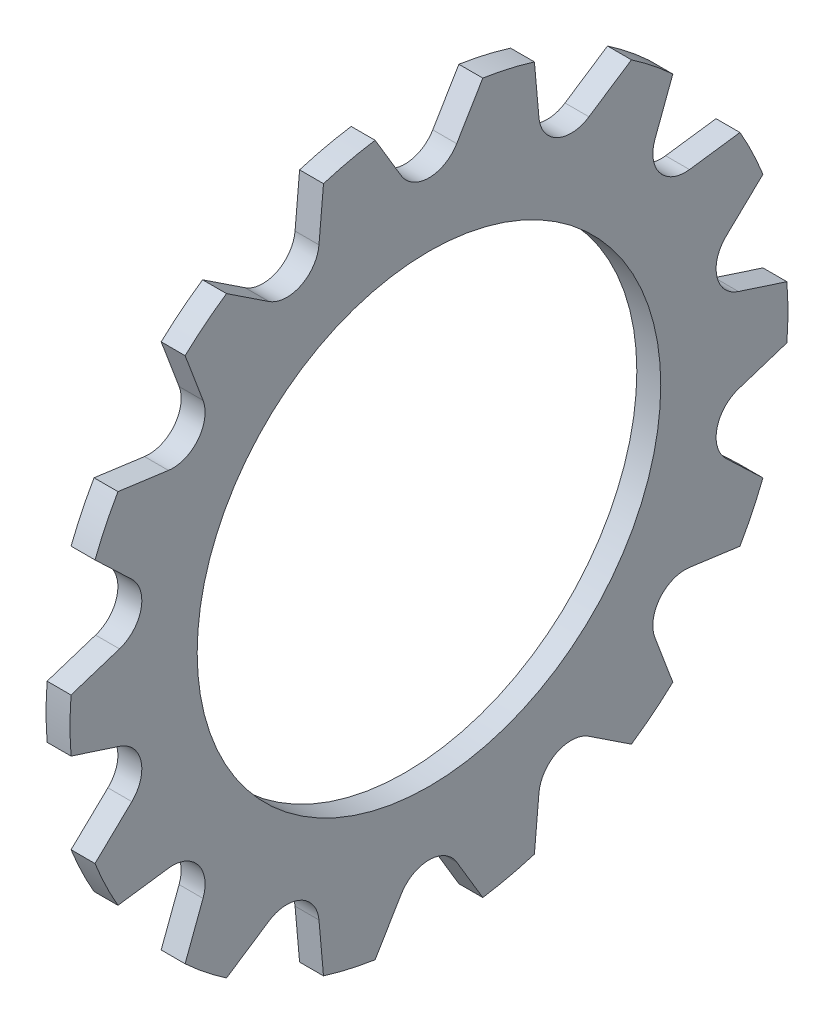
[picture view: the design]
ISO-10303-21;
HEADER;
FILE_DESCRIPTION(('STEP AP214'),'2;1');
FILE_NAME('part.step','',(''),(''),'','','');
FILE_SCHEMA(('AUTOMOTIVE_DESIGN { 1 0 10303 214 1 1 1 1 }'));
ENDSEC;
DATA;
#1=APPLICATION_CONTEXT('core data for automotive mechanical design processes');
#2=APPLICATION_PROTOCOL_DEFINITION('international standard','automotive_design',2000,#1);
#3=PRODUCT_CONTEXT('',#1,'mechanical');
#4=PRODUCT('Part','Part','',(#3));
#5=PRODUCT_RELATED_PRODUCT_CATEGORY('part','',(#4));
#6=PRODUCT_DEFINITION_FORMATION('','',#4);
#7=PRODUCT_DEFINITION_CONTEXT('part definition',#1,'design');
#8=PRODUCT_DEFINITION('design','',#6,#7);
#9=PRODUCT_DEFINITION_SHAPE('','',#8);
#10=(LENGTH_UNIT() NAMED_UNIT(*) SI_UNIT(.MILLI.,.METRE.));
#11=(NAMED_UNIT(*) PLANE_ANGLE_UNIT() SI_UNIT($,.RADIAN.));
#12=(NAMED_UNIT(*) SI_UNIT($,.STERADIAN.) SOLID_ANGLE_UNIT());
#13=UNCERTAINTY_MEASURE_WITH_UNIT(LENGTH_MEASURE(1.E-05),#10,'distance_accuracy_value','');
#14=(GEOMETRIC_REPRESENTATION_CONTEXT(3) GLOBAL_UNCERTAINTY_ASSIGNED_CONTEXT((#13)) GLOBAL_UNIT_ASSIGNED_CONTEXT((#10,
#11,#12)) REPRESENTATION_CONTEXT('',''));
#15=CARTESIAN_POINT('',(0.,0.,0.));
#16=DIRECTION('',(0.,0.,1.));
#17=DIRECTION('',(1.,0.,0.));
#18=AXIS2_PLACEMENT_3D('',#15,#16,#17);
#19=CARTESIAN_POINT('',(-1.6,0.,0.));
#20=DIRECTION('',(1.,0.,0.));
#21=DIRECTION('',(0.,0.,-1.));
#22=AXIS2_PLACEMENT_3D('',#19,#20,#21);
#23=CYLINDRICAL_SURFACE('',#22,24.);
#24=DIRECTION('',(1.,0.,0.));
#25=VECTOR('',#24,1.);
#26=CARTESIAN_POINT('',(-1.6,17.6090486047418,16.3070968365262));
#27=LINE('',#26,#25);
#28=CARTESIAN_POINT('',(-1.6,17.6090486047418,16.3070968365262));
#29=VERTEX_POINT('',#28);
#30=CARTESIAN_POINT('',(0.,17.6090486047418,16.3070968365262));
#31=VERTEX_POINT('',#30);
#32=EDGE_CURVE('E475',#29,#31,#27,.T.);
#33=ORIENTED_EDGE('',*,*,#32,.T.);
#34=CARTESIAN_POINT('',(0.,0.,0.));
#35=DIRECTION('',(1.,0.,0.));
#36=DIRECTION('',(0.,0.,-1.));
#37=AXIS2_PLACEMENT_3D('',#34,#35,#36);
#38=CIRCLE('',#37,24.);
#39=CARTESIAN_POINT('',(0.,19.8166258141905,13.5388825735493));
#40=VERTEX_POINT('',#39);
#41=EDGE_CURVE('E786',#40,#31,#38,.T.);
#42=ORIENTED_EDGE('',*,*,#41,.F.);
#43=DIRECTION('',(1.,0.,0.));
#44=VECTOR('',#43,1.);
#45=CARTESIAN_POINT('',(-1.6,19.8166258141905,13.5388825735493));
#46=LINE('',#45,#44);
#47=CARTESIAN_POINT('',(-1.6,19.8166258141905,13.5388825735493));
#48=VERTEX_POINT('',#47);
#49=EDGE_CURVE('E457',#48,#40,#46,.T.);
#50=ORIENTED_EDGE('',*,*,#49,.F.);
#51=CARTESIAN_POINT('',(-1.6,0.,0.));
#52=DIRECTION('',(1.,0.,0.));
#53=DIRECTION('',(0.,0.,-1.));
#54=AXIS2_PLACEMENT_3D('',#51,#52,#53);
#55=CIRCLE('',#54,24.);
#56=EDGE_CURVE('E41',#48,#29,#55,.T.);
#57=ORIENTED_EDGE('',*,*,#56,.T.);
#58=EDGE_LOOP('',(#33,#42,#50,#57));
#59=FACE_BOUND('',#58,.T.);
#60=ADVANCED_FACE('F32',(#59),#23,.T.);
#61=DIRECTION('',(1.,0.,0.));
#62=VECTOR('',#61,1.);
#63=CARTESIAN_POINT('',(-1.6,11.9798619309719,20.7962234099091));
#64=LINE('',#63,#62);
#65=CARTESIAN_POINT('',(-1.6,11.9798619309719,20.7962234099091));
#66=VERTEX_POINT('',#65);
#67=CARTESIAN_POINT('',(0.,11.9798619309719,20.7962234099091));
#68=VERTEX_POINT('',#67);
#69=EDGE_CURVE('E392',#66,#68,#64,.T.);
#70=ORIENTED_EDGE('',*,*,#69,.F.);
#71=CARTESIAN_POINT('',(-1.6,8.78982043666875,22.3324664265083));
#72=VERTEX_POINT('',#71);
#73=EDGE_CURVE('E407',#66,#72,#55,.T.);
#74=ORIENTED_EDGE('',*,*,#73,.T.);
#75=DIRECTION('',(1.,0.,0.));
#76=VECTOR('',#75,1.);
#77=CARTESIAN_POINT('',(-1.6,8.78982043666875,22.3324664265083));
#78=LINE('',#77,#76);
#79=CARTESIAN_POINT('',(0.,8.78982043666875,22.3324664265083));
#80=VERTEX_POINT('',#79);
#81=EDGE_CURVE('E746',#72,#80,#78,.T.);
#82=ORIENTED_EDGE('',*,*,#81,.T.);
#83=EDGE_CURVE('E409',#68,#80,#38,.T.);
#84=ORIENTED_EDGE('',*,*,#83,.F.);
#85=EDGE_LOOP('',(#70,#74,#82,#84));
#86=FACE_BOUND('',#85,.T.);
#87=ADVANCED_FACE('F405',(#86),#23,.T.);
#88=DIRECTION('',(1.,0.,0.));
#89=VECTOR('',#88,1.);
#90=CARTESIAN_POINT('',(-1.6,1.77033946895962,23.9346171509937));
#91=LINE('',#90,#89);
#92=CARTESIAN_POINT('',(-1.6,1.77033946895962,23.9346171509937));
#93=VERTEX_POINT('',#92);
#94=CARTESIAN_POINT('',(0.,1.77033946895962,23.9346171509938));
#95=VERTEX_POINT('',#94);
#96=EDGE_CURVE('E740',#93,#95,#91,.T.);
#97=ORIENTED_EDGE('',*,*,#96,.F.);
#98=CARTESIAN_POINT('',(-1.6,-1.77033946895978,23.9346171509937));
#99=VERTEX_POINT('',#98);
#100=EDGE_CURVE('E417',#93,#99,#55,.T.);
#101=ORIENTED_EDGE('',*,*,#100,.T.);
#102=DIRECTION('',(1.,0.,0.));
#103=VECTOR('',#102,1.);
#104=CARTESIAN_POINT('',(-1.6,-1.77033946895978,23.9346171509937));
#105=LINE('',#104,#103);
#106=CARTESIAN_POINT('',(0.,-1.77033946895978,23.9346171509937));
#107=VERTEX_POINT('',#106);
#108=EDGE_CURVE('E721',#99,#107,#105,.T.);
#109=ORIENTED_EDGE('',*,*,#108,.T.);
#110=EDGE_CURVE('E793',#95,#107,#38,.T.);
#111=ORIENTED_EDGE('',*,*,#110,.F.);
#112=EDGE_LOOP('',(#97,#101,#109,#111));
#113=FACE_BOUND('',#112,.T.);
#114=ADVANCED_FACE('F988',(#113),#23,.T.);
#115=DIRECTION('',(1.,0.,0.));
#116=VECTOR('',#115,1.);
#117=CARTESIAN_POINT('',(-1.6,-8.78982043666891,22.3324664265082));
#118=LINE('',#117,#116);
#119=CARTESIAN_POINT('',(-1.6,-8.78982043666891,22.3324664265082));
#120=VERTEX_POINT('',#119);
#121=CARTESIAN_POINT('',(0.,-8.78982043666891,22.3324664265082));
#122=VERTEX_POINT('',#121);
#123=EDGE_CURVE('E714',#120,#122,#118,.T.);
#124=ORIENTED_EDGE('',*,*,#123,.F.);
#125=CARTESIAN_POINT('',(-1.6,-11.9798619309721,20.796223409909));
#126=VERTEX_POINT('',#125);
#127=EDGE_CURVE('E420',#120,#126,#55,.T.);
#128=ORIENTED_EDGE('',*,*,#127,.T.);
#129=DIRECTION('',(1.,0.,0.));
#130=VECTOR('',#129,1.);
#131=CARTESIAN_POINT('',(-1.6,-11.9798619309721,20.796223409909));
#132=LINE('',#131,#130);
#133=CARTESIAN_POINT('',(0.,-11.9798619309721,20.796223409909));
#134=VERTEX_POINT('',#133);
#135=EDGE_CURVE('E695',#126,#134,#132,.T.);
#136=ORIENTED_EDGE('',*,*,#135,.T.);
#137=EDGE_CURVE('E796',#122,#134,#38,.T.);
#138=ORIENTED_EDGE('',*,*,#137,.F.);
#139=EDGE_LOOP('',(#124,#128,#136,#138));
#140=FACE_BOUND('',#139,.T.);
#141=ADVANCED_FACE('F896',(#140),#23,.T.);
#142=DIRECTION('',(1.,0.,0.));
#143=VECTOR('',#142,1.);
#144=CARTESIAN_POINT('',(-1.6,-17.6090486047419,16.3070968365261));
#145=LINE('',#144,#143);
#146=CARTESIAN_POINT('',(-1.6,-17.6090486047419,16.3070968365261));
#147=VERTEX_POINT('',#146);
#148=CARTESIAN_POINT('',(0.,-17.6090486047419,16.3070968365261));
#149=VERTEX_POINT('',#148);
#150=EDGE_CURVE('E688',#147,#149,#145,.T.);
#151=ORIENTED_EDGE('',*,*,#150,.F.);
#152=CARTESIAN_POINT('',(-1.6,-19.8166258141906,13.5388825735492));
#153=VERTEX_POINT('',#152);
#154=EDGE_CURVE('E884',#147,#153,#55,.T.);
#155=ORIENTED_EDGE('',*,*,#154,.T.);
#156=DIRECTION('',(1.,0.,0.));
#157=VECTOR('',#156,1.);
#158=CARTESIAN_POINT('',(-1.6,-19.8166258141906,13.5388825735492));
#159=LINE('',#158,#157);
#160=CARTESIAN_POINT('',(0.,-19.8166258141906,13.5388825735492));
#161=VERTEX_POINT('',#160);
#162=EDGE_CURVE('E669',#153,#161,#159,.T.);
#163=ORIENTED_EDGE('',*,*,#162,.T.);
#164=EDGE_CURVE('E801',#149,#161,#38,.T.);
#165=ORIENTED_EDGE('',*,*,#164,.F.);
#166=EDGE_LOOP('',(#151,#155,#163,#165));
#167=FACE_BOUND('',#166,.T.);
#168=ADVANCED_FACE('F906',(#167),#23,.T.);
#169=DIRECTION('',(1.,0.,0.));
#170=VECTOR('',#169,1.);
#171=CARTESIAN_POINT('',(-1.6,-22.940588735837,7.05190672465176));
#172=LINE('',#171,#170);
#173=CARTESIAN_POINT('',(-1.6,-22.940588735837,7.05190672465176));
#174=VERTEX_POINT('',#173);
#175=CARTESIAN_POINT('',(0.,-22.940588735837,7.05190672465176));
#176=VERTEX_POINT('',#175);
#177=EDGE_CURVE('E662',#174,#176,#172,.T.);
#178=ORIENTED_EDGE('',*,*,#177,.F.);
#179=CARTESIAN_POINT('',(-1.6,-23.7284639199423,3.59999999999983));
#180=VERTEX_POINT('',#179);
#181=EDGE_CURVE('E879',#174,#180,#55,.T.);
#182=ORIENTED_EDGE('',*,*,#181,.T.);
#183=DIRECTION('',(1.,0.,0.));
#184=VECTOR('',#183,1.);
#185=CARTESIAN_POINT('',(-1.6,-23.7284639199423,3.59999999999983));
#186=LINE('',#185,#184);
#187=CARTESIAN_POINT('',(0.,-23.7284639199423,3.59999999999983));
#188=VERTEX_POINT('',#187);
#189=EDGE_CURVE('E643',#180,#188,#186,.T.);
#190=ORIENTED_EDGE('',*,*,#189,.T.);
#191=EDGE_CURVE('E806',#176,#188,#38,.T.);
#192=ORIENTED_EDGE('',*,*,#191,.F.);
#193=EDGE_LOOP('',(#178,#182,#190,#192));
#194=FACE_BOUND('',#193,.T.);
#195=ADVANCED_FACE('F916',(#194),#23,.T.);
#196=DIRECTION('',(1.,0.,0.));
#197=VECTOR('',#196,1.);
#198=CARTESIAN_POINT('',(-1.6,-23.7284639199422,-3.60000000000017));
#199=LINE('',#198,#197);
#200=CARTESIAN_POINT('',(-1.6,-23.7284639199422,-3.60000000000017));
#201=VERTEX_POINT('',#200);
#202=CARTESIAN_POINT('',(0.,-23.7284639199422,-3.60000000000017));
#203=VERTEX_POINT('',#202);
#204=EDGE_CURVE('E636',#201,#203,#199,.T.);
#205=ORIENTED_EDGE('',*,*,#204,.F.);
#206=CARTESIAN_POINT('',(-1.6,-22.9405887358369,-7.05190672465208));
#207=VERTEX_POINT('',#206);
#208=EDGE_CURVE('E874',#201,#207,#55,.T.);
#209=ORIENTED_EDGE('',*,*,#208,.T.);
#210=DIRECTION('',(1.,0.,0.));
#211=VECTOR('',#210,1.);
#212=CARTESIAN_POINT('',(-1.6,-22.9405887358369,-7.05190672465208));
#213=LINE('',#212,#211);
#214=CARTESIAN_POINT('',(0.,-22.9405887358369,-7.05190672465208));
#215=VERTEX_POINT('',#214);
#216=EDGE_CURVE('E617',#207,#215,#213,.T.);
#217=ORIENTED_EDGE('',*,*,#216,.T.);
#218=EDGE_CURVE('E811',#203,#215,#38,.T.);
#219=ORIENTED_EDGE('',*,*,#218,.F.);
#220=EDGE_LOOP('',(#205,#209,#217,#219));
#221=FACE_BOUND('',#220,.T.);
#222=ADVANCED_FACE('F926',(#221),#23,.T.);
#223=DIRECTION('',(1.,0.,0.));
#224=VECTOR('',#223,1.);
#225=CARTESIAN_POINT('',(-1.6,-19.8166258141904,-13.5388825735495));
#226=LINE('',#225,#224);
#227=CARTESIAN_POINT('',(-1.6,-19.8166258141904,-13.5388825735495));
#228=VERTEX_POINT('',#227);
#229=CARTESIAN_POINT('',(0.,-19.8166258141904,-13.5388825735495));
#230=VERTEX_POINT('',#229);
#231=EDGE_CURVE('E610',#228,#230,#226,.T.);
#232=ORIENTED_EDGE('',*,*,#231,.F.);
#233=CARTESIAN_POINT('',(-1.6,-17.6090486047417,-16.3070968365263));
#234=VERTEX_POINT('',#233);
#235=EDGE_CURVE('E869',#228,#234,#55,.T.);
#236=ORIENTED_EDGE('',*,*,#235,.T.);
#237=DIRECTION('',(1.,0.,0.));
#238=VECTOR('',#237,1.);
#239=CARTESIAN_POINT('',(-1.6,-17.6090486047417,-16.3070968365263));
#240=LINE('',#239,#238);
#241=CARTESIAN_POINT('',(0.,-17.6090486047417,-16.3070968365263));
#242=VERTEX_POINT('',#241);
#243=EDGE_CURVE('E591',#234,#242,#240,.T.);
#244=ORIENTED_EDGE('',*,*,#243,.T.);
#245=EDGE_CURVE('E816',#230,#242,#38,.T.);
#246=ORIENTED_EDGE('',*,*,#245,.F.);
#247=EDGE_LOOP('',(#232,#236,#244,#246));
#248=FACE_BOUND('',#247,.T.);
#249=ADVANCED_FACE('F936',(#248),#23,.T.);
#250=DIRECTION('',(1.,0.,0.));
#251=VECTOR('',#250,1.);
#252=CARTESIAN_POINT('',(-1.6,-11.9798619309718,-20.7962234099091));
#253=LINE('',#252,#251);
#254=CARTESIAN_POINT('',(-1.6,-11.9798619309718,-20.7962234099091));
#255=VERTEX_POINT('',#254);
#256=CARTESIAN_POINT('',(0.,-11.9798619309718,-20.7962234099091));
#257=VERTEX_POINT('',#256);
#258=EDGE_CURVE('E584',#255,#257,#253,.T.);
#259=ORIENTED_EDGE('',*,*,#258,.F.);
#260=CARTESIAN_POINT('',(-1.6,-8.7898204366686,-22.3324664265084));
#261=VERTEX_POINT('',#260);
#262=EDGE_CURVE('E864',#255,#261,#55,.T.);
#263=ORIENTED_EDGE('',*,*,#262,.T.);
#264=DIRECTION('',(1.,0.,0.));
#265=VECTOR('',#264,1.);
#266=CARTESIAN_POINT('',(-1.6,-8.7898204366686,-22.3324664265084));
#267=LINE('',#266,#265);
#268=CARTESIAN_POINT('',(0.,-8.7898204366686,-22.3324664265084));
#269=VERTEX_POINT('',#268);
#270=EDGE_CURVE('E565',#261,#269,#267,.T.);
#271=ORIENTED_EDGE('',*,*,#270,.T.);
#272=EDGE_CURVE('E821',#257,#269,#38,.T.);
#273=ORIENTED_EDGE('',*,*,#272,.F.);
#274=EDGE_LOOP('',(#259,#263,#271,#273));
#275=FACE_BOUND('',#274,.T.);
#276=ADVANCED_FACE('F946',(#275),#23,.T.);
#277=DIRECTION('',(1.,0.,0.));
#278=VECTOR('',#277,1.);
#279=CARTESIAN_POINT('',(-1.6,-1.77033946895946,-23.9346171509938));
#280=LINE('',#279,#278);
#281=CARTESIAN_POINT('',(-1.6,-1.77033946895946,-23.9346171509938));
#282=VERTEX_POINT('',#281);
#283=CARTESIAN_POINT('',(0.,-1.77033946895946,-23.9346171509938));
#284=VERTEX_POINT('',#283);
#285=EDGE_CURVE('E558',#282,#284,#280,.T.);
#286=ORIENTED_EDGE('',*,*,#285,.F.);
#287=CARTESIAN_POINT('',(-1.6,1.77033946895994,-23.9346171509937));
#288=VERTEX_POINT('',#287);
#289=EDGE_CURVE('E859',#282,#288,#55,.T.);
#290=ORIENTED_EDGE('',*,*,#289,.T.);
#291=DIRECTION('',(1.,0.,0.));
#292=VECTOR('',#291,1.);
#293=CARTESIAN_POINT('',(-1.6,1.77033946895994,-23.9346171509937));
#294=LINE('',#293,#292);
#295=CARTESIAN_POINT('',(0.,1.77033946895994,-23.9346171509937));
#296=VERTEX_POINT('',#295);
#297=EDGE_CURVE('E539',#288,#296,#294,.T.);
#298=ORIENTED_EDGE('',*,*,#297,.T.);
#299=EDGE_CURVE('E826',#284,#296,#38,.T.);
#300=ORIENTED_EDGE('',*,*,#299,.F.);
#301=EDGE_LOOP('',(#286,#290,#298,#300));
#302=FACE_BOUND('',#301,.T.);
#303=ADVANCED_FACE('F956',(#302),#23,.T.);
#304=DIRECTION('',(1.,0.,0.));
#305=VECTOR('',#304,1.);
#306=CARTESIAN_POINT('',(-1.6,8.78982043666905,-22.3324664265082));
#307=LINE('',#306,#305);
#308=CARTESIAN_POINT('',(-1.6,8.78982043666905,-22.3324664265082));
#309=VERTEX_POINT('',#308);
#310=CARTESIAN_POINT('',(0.,8.78982043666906,-22.3324664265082));
#311=VERTEX_POINT('',#310);
#312=EDGE_CURVE('E532',#309,#311,#307,.T.);
#313=ORIENTED_EDGE('',*,*,#312,.F.);
#314=CARTESIAN_POINT('',(-1.6,11.9798619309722,-20.7962234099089));
#315=VERTEX_POINT('',#314);
#316=EDGE_CURVE('E855',#309,#315,#55,.T.);
#317=ORIENTED_EDGE('',*,*,#316,.T.);
#318=DIRECTION('',(1.,0.,0.));
#319=VECTOR('',#318,1.);
#320=CARTESIAN_POINT('',(-1.6,11.9798619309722,-20.7962234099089));
#321=LINE('',#320,#319);
#322=CARTESIAN_POINT('',(0.,11.9798619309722,-20.7962234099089));
#323=VERTEX_POINT('',#322);
#324=EDGE_CURVE('E514',#315,#323,#321,.T.);
#325=ORIENTED_EDGE('',*,*,#324,.T.);
#326=EDGE_CURVE('E831',#311,#323,#38,.T.);
#327=ORIENTED_EDGE('',*,*,#326,.F.);
#328=EDGE_LOOP('',(#313,#317,#325,#327));
#329=FACE_BOUND('',#328,.T.);
#330=ADVANCED_FACE('F966',(#329),#23,.T.);
#331=DIRECTION('',(1.,0.,0.));
#332=VECTOR('',#331,1.);
#333=CARTESIAN_POINT('',(-1.6,17.609048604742,-16.3070968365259));
#334=LINE('',#333,#332);
#335=CARTESIAN_POINT('',(-1.6,17.609048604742,-16.3070968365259));
#336=VERTEX_POINT('',#335);
#337=CARTESIAN_POINT('',(0.,17.609048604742,-16.3070968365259));
#338=VERTEX_POINT('',#337);
#339=EDGE_CURVE('E57',#336,#338,#334,.T.);
#340=ORIENTED_EDGE('',*,*,#339,.F.);
#341=CARTESIAN_POINT('',(-1.6,19.8166258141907,-13.5388825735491));
#342=VERTEX_POINT('',#341);
#343=EDGE_CURVE('E853',#336,#342,#55,.T.);
#344=ORIENTED_EDGE('',*,*,#343,.T.);
#345=DIRECTION('',(1.,0.,0.));
#346=VECTOR('',#345,1.);
#347=CARTESIAN_POINT('',(-1.6,19.8166258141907,-13.5388825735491));
#348=LINE('',#347,#346);
#349=CARTESIAN_POINT('',(0.,19.8166258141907,-13.5388825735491));
#350=VERTEX_POINT('',#349);
#351=EDGE_CURVE('E489',#342,#350,#348,.T.);
#352=ORIENTED_EDGE('',*,*,#351,.T.);
#353=EDGE_CURVE('E836',#338,#350,#38,.T.);
#354=ORIENTED_EDGE('',*,*,#353,.F.);
#355=EDGE_LOOP('',(#340,#344,#352,#354));
#356=FACE_BOUND('',#355,.T.);
#357=ADVANCED_FACE('F997',(#356),#23,.T.);
#358=DIRECTION('',(1.,0.,0.));
#359=VECTOR('',#358,1.);
#360=CARTESIAN_POINT('',(-1.6,22.940588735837,7.05190672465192));
#361=LINE('',#360,#359);
#362=CARTESIAN_POINT('',(-1.6,22.940588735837,7.05190672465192));
#363=VERTEX_POINT('',#362);
#364=CARTESIAN_POINT('',(0.,22.940588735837,7.05190672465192));
#365=VERTEX_POINT('',#364);
#366=EDGE_CURVE('E449',#363,#365,#361,.T.);
#367=ORIENTED_EDGE('',*,*,#366,.T.);
#368=CARTESIAN_POINT('',(0.,23.7284639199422,3.6));
#369=VERTEX_POINT('',#368);
#370=EDGE_CURVE('E36',#369,#365,#38,.T.);
#371=ORIENTED_EDGE('',*,*,#370,.F.);
#372=DIRECTION('',(1.,0.,0.));
#373=VECTOR('',#372,1.);
#374=CARTESIAN_POINT('',(-1.6,23.7284639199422,3.6));
#375=LINE('',#374,#373);
#376=CARTESIAN_POINT('',(-1.6,23.7284639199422,3.6));
#377=VERTEX_POINT('',#376);
#378=EDGE_CURVE('E430',#377,#369,#375,.T.);
#379=ORIENTED_EDGE('',*,*,#378,.F.);
#380=EDGE_CURVE('E11',#377,#363,#55,.T.);
#381=ORIENTED_EDGE('',*,*,#380,.T.);
#382=EDGE_LOOP('',(#367,#371,#379,#381));
#383=FACE_BOUND('',#382,.T.);
#384=ADVANCED_FACE('F990',(#383),#23,.T.);
#385=DIRECTION('',(1.,0.,0.));
#386=VECTOR('',#385,1.);
#387=CARTESIAN_POINT('',(-1.6,22.940588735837,-7.0519067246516));
#388=LINE('',#387,#386);
#389=CARTESIAN_POINT('',(-1.6,22.940588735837,-7.0519067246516));
#390=VERTEX_POINT('',#389);
#391=CARTESIAN_POINT('',(0.,22.9405887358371,-7.0519067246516));
#392=VERTEX_POINT('',#391);
#393=EDGE_CURVE('E49',#390,#392,#388,.T.);
#394=ORIENTED_EDGE('',*,*,#393,.F.);
#395=CARTESIAN_POINT('',(-1.6,23.7284639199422,-3.6));
#396=VERTEX_POINT('',#395);
#397=EDGE_CURVE('E42',#390,#396,#55,.T.);
#398=ORIENTED_EDGE('',*,*,#397,.T.);
#399=DIRECTION('',(1.,0.,0.));
#400=VECTOR('',#399,1.);
#401=CARTESIAN_POINT('',(-1.6,23.7284639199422,-3.6));
#402=LINE('',#401,#400);
#403=CARTESIAN_POINT('',(0.,23.7284639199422,-3.6));
#404=VERTEX_POINT('',#403);
#405=EDGE_CURVE('E426',#396,#404,#402,.T.);
#406=ORIENTED_EDGE('',*,*,#405,.T.);
#407=EDGE_CURVE('E429',#392,#404,#38,.T.);
#408=ORIENTED_EDGE('',*,*,#407,.F.);
#409=EDGE_LOOP('',(#394,#398,#406,#408));
#410=FACE_BOUND('',#409,.T.);
#411=ADVANCED_FACE('F34',(#410),#23,.T.);
#412=CARTESIAN_POINT('',(-1.6,0.,0.));
#413=DIRECTION('',(1.,0.,0.));
#414=DIRECTION('',(0.,0.,-1.));
#415=AXIS2_PLACEMENT_3D('',#412,#413,#414);
#416=PLANE('',#415);
#417=CARTESIAN_POINT('',(-1.6,0.,0.));
#418=DIRECTION('',(1.,0.,0.));
#419=DIRECTION('',(0.,0.,-1.));
#420=AXIS2_PLACEMENT_3D('',#417,#418,#419);
#421=CIRCLE('',#420,15.5);
#422=CARTESIAN_POINT('',(-1.6,0.,-15.5));
#423=VERTEX_POINT('',#422);
#424=EDGE_CURVE('E425',#423,#423,#421,.T.);
#425=ORIENTED_EDGE('',*,*,#424,.T.);
#426=EDGE_LOOP('',(#425));
#427=FACE_BOUND('',#426,.T.);
#428=CARTESIAN_POINT('',(-1.6,13.6606615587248,17.1299277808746));
#429=DIRECTION('',(1.,0.,0.));
#430=DIRECTION('',(0.,0.781831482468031,-0.623489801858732));
#431=AXIS2_PLACEMENT_3D('',#428,#429,#430);
#432=CIRCLE('',#431,2.16);
#433=CARTESIAN_POINT('',(-1.6,11.520404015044,17.4212997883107));
#434=VERTEX_POINT('',#433);
#435=CARTESIAN_POINT('',(-1.6,14.4209803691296,15.1081673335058));
#436=VERTEX_POINT('',#435);
#437=EDGE_CURVE('E399',#434,#436,#432,.T.);
#438=ORIENTED_EDGE('',*,*,#437,.T.);
#439=DIRECTION('',(0.,0.936000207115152,0.35199944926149));
#440=VECTOR('',#439,1.);
#441=CARTESIAN_POINT('',(-1.6,14.4209803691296,15.1081673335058));
#442=LINE('',#441,#440);
#443=EDGE_CURVE('E410',#436,#29,#442,.T.);
#444=ORIENTED_EDGE('',*,*,#443,.T.);
#445=ORIENTED_EDGE('',*,*,#56,.F.);
#446=DIRECTION('',(0.,-0.551453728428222,-0.834205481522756));
#447=VECTOR('',#446,1.);
#448=CARTESIAN_POINT('',(-1.6,17.9383440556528,10.6975327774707));
#449=LINE('',#448,#447);
#450=CARTESIAN_POINT('',(-1.6,17.9383440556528,10.6975327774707));
#451=VERTEX_POINT('',#450);
#452=EDGE_CURVE('E468',#48,#451,#449,.T.);
#453=ORIENTED_EDGE('',*,*,#452,.T.);
#454=CARTESIAN_POINT('',(-1.6,19.740227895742,9.50639272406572));
#455=DIRECTION('',(1.,0.,0.));
#456=DIRECTION('',(0.,0.433883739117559,-0.900968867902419));
#457=AXIS2_PLACEMENT_3D('',#454,#455,#456);
#458=CIRCLE('',#457,2.16);
#459=CARTESIAN_POINT('',(-1.6,19.548042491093,7.35495953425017));
#460=VERTEX_POINT('',#459);
#461=EDGE_CURVE('E478',#451,#460,#458,.T.);
#462=ORIENTED_EDGE('',*,*,#461,.T.);
#463=DIRECTION('',(0.,0.996033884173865,-0.0889747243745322));
#464=VECTOR('',#463,1.);
#465=CARTESIAN_POINT('',(-1.6,19.548042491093,7.35495953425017));
#466=LINE('',#465,#464);
#467=EDGE_CURVE('E460',#460,#363,#466,.T.);
#468=ORIENTED_EDGE('',*,*,#467,.T.);
#469=ORIENTED_EDGE('',*,*,#380,.F.);
#470=DIRECTION('',(0.,-0.858790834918,-0.512326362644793));
#471=VECTOR('',#470,1.);
#472=CARTESIAN_POINT('',(-1.6,20.8033750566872,1.85498820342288));
#473=LINE('',#472,#471);
#474=CARTESIAN_POINT('',(-1.6,20.8033750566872,1.85498820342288));
#475=VERTEX_POINT('',#474);
#476=EDGE_CURVE('E442',#377,#475,#473,.T.);
#477=ORIENTED_EDGE('',*,*,#476,.T.);
#478=CARTESIAN_POINT('',(-1.6,21.91,0.));
#479=DIRECTION('',(1.,0.,0.));
#480=DIRECTION('',(0.,0.,-1.));
#481=AXIS2_PLACEMENT_3D('',#478,#479,#480);
#482=CIRCLE('',#481,2.16);
#483=CARTESIAN_POINT('',(-1.6,20.8033750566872,-1.85498820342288));
#484=VERTEX_POINT('',#483);
#485=EDGE_CURVE('E452',#475,#484,#482,.T.);
#486=ORIENTED_EDGE('',*,*,#485,.T.);
#487=DIRECTION('',(0.,0.858790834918,-0.512326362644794));
#488=VECTOR('',#487,1.);
#489=CARTESIAN_POINT('',(-1.6,20.8033750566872,-1.85498820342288));
#490=LINE('',#489,#488);
#491=EDGE_CURVE('E433',#484,#396,#490,.T.);
#492=ORIENTED_EDGE('',*,*,#491,.T.);
#493=ORIENTED_EDGE('',*,*,#397,.F.);
#494=DIRECTION('',(0.,-0.996033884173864,-0.088974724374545));
#495=VECTOR('',#494,1.);
#496=CARTESIAN_POINT('',(-1.6,19.5480424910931,-7.35495953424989));
#497=LINE('',#496,#495);
#498=CARTESIAN_POINT('',(-1.6,19.5480424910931,-7.35495953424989));
#499=VERTEX_POINT('',#498);
#500=EDGE_CURVE('E495',#390,#499,#497,.T.);
#501=ORIENTED_EDGE('',*,*,#500,.T.);
#502=CARTESIAN_POINT('',(-1.6,19.7402278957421,-9.50639272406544));
#503=DIRECTION('',(1.,0.,0.));
#504=DIRECTION('',(0.,-0.433883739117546,-0.900968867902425));
#505=AXIS2_PLACEMENT_3D('',#502,#503,#504);
#506=CIRCLE('',#505,2.16);
#507=CARTESIAN_POINT('',(-1.6,17.938344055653,-10.6975327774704));
#508=VERTEX_POINT('',#507);
#509=EDGE_CURVE('E503',#499,#508,#506,.T.);
#510=ORIENTED_EDGE('',*,*,#509,.T.);
#511=DIRECTION('',(0.,0.551453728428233,-0.834205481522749));
#512=VECTOR('',#511,1.);
#513=CARTESIAN_POINT('',(-1.6,17.938344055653,-10.6975327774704));
#514=LINE('',#513,#512);
#515=EDGE_CURVE('E485',#508,#342,#514,.T.);
#516=ORIENTED_EDGE('',*,*,#515,.T.);
#517=ORIENTED_EDGE('',*,*,#343,.F.);
#518=DIRECTION('',(0.,-0.936000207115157,0.351999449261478));
#519=VECTOR('',#518,1.);
#520=CARTESIAN_POINT('',(-1.6,14.4209803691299,-15.1081673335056));
#521=LINE('',#520,#519);
#522=CARTESIAN_POINT('',(-1.6,14.4209803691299,-15.1081673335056));
#523=VERTEX_POINT('',#522);
#524=EDGE_CURVE('E520',#336,#523,#521,.T.);
#525=ORIENTED_EDGE('',*,*,#524,.T.);
#526=CARTESIAN_POINT('',(-1.6,13.6606615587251,-17.1299277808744));
#527=DIRECTION('',(1.,0.,0.));
#528=DIRECTION('',(0.,-0.781831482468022,-0.623489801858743));
#529=AXIS2_PLACEMENT_3D('',#526,#527,#528);
#530=CIRCLE('',#529,2.16);
#531=CARTESIAN_POINT('',(-1.6,11.5204040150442,-17.4212997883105));
#532=VERTEX_POINT('',#531);
#533=EDGE_CURVE('E527',#523,#532,#530,.T.);
#534=ORIENTED_EDGE('',*,*,#533,.T.);
#535=DIRECTION('',(0.,0.134894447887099,-0.990859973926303));
#536=VECTOR('',#535,1.);
#537=CARTESIAN_POINT('',(-1.6,11.5204040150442,-17.4212997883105));
#538=LINE('',#537,#536);
#539=EDGE_CURVE('E510',#532,#315,#538,.T.);
#540=ORIENTED_EDGE('',*,*,#539,.T.);
#541=ORIENTED_EDGE('',*,*,#316,.F.);
#542=DIRECTION('',(0.,-0.69058020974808,0.723255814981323));
#543=VECTOR('',#542,1.);
#544=CARTESIAN_POINT('',(-1.6,6.43766622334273,-19.8690173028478));
#545=LINE('',#544,#543);
#546=CARTESIAN_POINT('',(-1.6,6.43766622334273,-19.8690173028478));
#547=VERTEX_POINT('',#546);
#548=EDGE_CURVE('E545',#309,#547,#545,.T.);
#549=ORIENTED_EDGE('',*,*,#548,.T.);
#550=CARTESIAN_POINT('',(-1.6,4.87543366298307,-21.3606705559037));
#551=DIRECTION('',(1.,0.,0.));
#552=DIRECTION('',(0.,-0.974927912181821,-0.222520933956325));
#553=AXIS2_PLACEMENT_3D('',#550,#551,#552);
#554=CIRCLE('',#553,2.16);
#555=CARTESIAN_POINT('',(-1.6,2.82070667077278,-20.6945647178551));
#556=VERTEX_POINT('',#555);
#557=EDGE_CURVE('E553',#547,#556,#554,.T.);
#558=ORIENTED_EDGE('',*,*,#557,.T.);
#559=DIRECTION('',(0.,-0.308382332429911,-0.951262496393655));
#560=VECTOR('',#559,1.);
#561=CARTESIAN_POINT('',(-1.6,2.82070667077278,-20.6945647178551));
#562=LINE('',#561,#560);
#563=EDGE_CURVE('E535',#556,#288,#562,.T.);
#564=ORIENTED_EDGE('',*,*,#563,.T.);
#565=ORIENTED_EDGE('',*,*,#289,.F.);
#566=DIRECTION('',(0.,-0.308382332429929,0.951262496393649));
#567=VECTOR('',#566,1.);
#568=CARTESIAN_POINT('',(-1.6,-2.82070667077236,-20.6945647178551));
#569=LINE('',#568,#567);
#570=CARTESIAN_POINT('',(-1.6,-2.82070667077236,-20.6945647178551));
#571=VERTEX_POINT('',#570);
#572=EDGE_CURVE('E571',#282,#571,#569,.T.);
#573=ORIENTED_EDGE('',*,*,#572,.T.);
#574=CARTESIAN_POINT('',(-1.6,-4.87543366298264,-21.3606705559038));
#575=DIRECTION('',(1.,0.,0.));
#576=DIRECTION('',(0.,-0.974927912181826,0.222520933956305));
#577=AXIS2_PLACEMENT_3D('',#574,#575,#576);
#578=CIRCLE('',#577,2.16);
#579=CARTESIAN_POINT('',(-1.6,-6.43766622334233,-19.869017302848));
#580=VERTEX_POINT('',#579);
#581=EDGE_CURVE('E579',#571,#580,#578,.T.);
#582=ORIENTED_EDGE('',*,*,#581,.T.);
#583=DIRECTION('',(0.,-0.690580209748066,-0.723255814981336));
#584=VECTOR('',#583,1.);
#585=CARTESIAN_POINT('',(-1.6,-6.43766622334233,-19.869017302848));
#586=LINE('',#585,#584);
#587=EDGE_CURVE('E561',#580,#261,#586,.T.);
#588=ORIENTED_EDGE('',*,*,#587,.T.);
#589=ORIENTED_EDGE('',*,*,#262,.F.);
#590=DIRECTION('',(0.,0.13489444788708,0.990859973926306));
#591=VECTOR('',#590,1.);
#592=CARTESIAN_POINT('',(-1.6,-11.5204040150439,-17.4212997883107));
#593=LINE('',#592,#591);
#594=CARTESIAN_POINT('',(-1.6,-11.5204040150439,-17.4212997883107));
#595=VERTEX_POINT('',#594);
#596=EDGE_CURVE('E597',#255,#595,#593,.T.);
#597=ORIENTED_EDGE('',*,*,#596,.T.);
#598=CARTESIAN_POINT('',(-1.6,-13.6606615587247,-17.1299277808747));
#599=DIRECTION('',(1.,0.,0.));
#600=DIRECTION('',(0.,-0.781831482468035,0.623489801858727));
#601=AXIS2_PLACEMENT_3D('',#598,#599,#600);
#602=CIRCLE('',#601,2.16);
#603=CARTESIAN_POINT('',(-1.6,-14.4209803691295,-15.1081673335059));
#604=VERTEX_POINT('',#603);
#605=EDGE_CURVE('E605',#595,#604,#602,.T.);
#606=ORIENTED_EDGE('',*,*,#605,.T.);
#607=DIRECTION('',(0.,-0.93600020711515,-0.351999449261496));
#608=VECTOR('',#607,1.);
#609=CARTESIAN_POINT('',(-1.6,-14.4209803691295,-15.1081673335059));
#610=LINE('',#609,#608);
#611=EDGE_CURVE('E587',#604,#234,#610,.T.);
#612=ORIENTED_EDGE('',*,*,#611,.T.);
#613=ORIENTED_EDGE('',*,*,#235,.F.);
#614=DIRECTION('',(0.,0.551453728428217,0.834205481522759));
#615=VECTOR('',#614,1.);
#616=CARTESIAN_POINT('',(-1.6,-17.9383440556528,-10.6975327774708));
#617=LINE('',#616,#615);
#618=CARTESIAN_POINT('',(-1.6,-17.9383440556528,-10.6975327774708));
#619=VERTEX_POINT('',#618);
#620=EDGE_CURVE('E623',#228,#619,#617,.T.);
#621=ORIENTED_EDGE('',*,*,#620,.T.);
#622=CARTESIAN_POINT('',(-1.6,-19.7402278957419,-9.50639272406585));
#623=DIRECTION('',(1.,0.,0.));
#624=DIRECTION('',(0.,-0.433883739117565,0.900968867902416));
#625=AXIS2_PLACEMENT_3D('',#622,#623,#624);
#626=CIRCLE('',#625,2.16);
#627=CARTESIAN_POINT('',(-1.6,-19.548042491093,-7.3549595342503));
#628=VERTEX_POINT('',#627);
#629=EDGE_CURVE('E631',#619,#628,#626,.T.);
#630=ORIENTED_EDGE('',*,*,#629,.T.);
#631=DIRECTION('',(0.,-0.996033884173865,0.0889747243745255));
#632=VECTOR('',#631,1.);
#633=CARTESIAN_POINT('',(-1.6,-19.548042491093,-7.3549595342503));
#634=LINE('',#633,#632);
#635=EDGE_CURVE('E613',#628,#207,#634,.T.);
#636=ORIENTED_EDGE('',*,*,#635,.T.);
#637=ORIENTED_EDGE('',*,*,#208,.F.);
#638=DIRECTION('',(0.,0.858790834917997,0.512326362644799));
#639=VECTOR('',#638,1.);
#640=CARTESIAN_POINT('',(-1.6,-20.8033750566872,-1.85498820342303));
#641=LINE('',#640,#639);
#642=CARTESIAN_POINT('',(-1.6,-20.8033750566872,-1.85498820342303));
#643=VERTEX_POINT('',#642);
#644=EDGE_CURVE('E649',#201,#643,#641,.T.);
#645=ORIENTED_EDGE('',*,*,#644,.T.);
#646=CARTESIAN_POINT('',(-1.6,-21.91,-1.52996712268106E-13));
#647=DIRECTION('',(1.,0.,0.));
#648=DIRECTION('',(0.,0.,1.));
#649=AXIS2_PLACEMENT_3D('',#646,#647,#648);
#650=CIRCLE('',#649,2.16);
#651=CARTESIAN_POINT('',(-1.6,-20.8033750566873,1.85498820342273));
#652=VERTEX_POINT('',#651);
#653=EDGE_CURVE('E657',#643,#652,#650,.T.);
#654=ORIENTED_EDGE('',*,*,#653,.T.);
#655=DIRECTION('',(0.,-0.858790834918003,0.512326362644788));
#656=VECTOR('',#655,1.);
#657=CARTESIAN_POINT('',(-1.6,-20.8033750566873,1.85498820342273));
#658=LINE('',#657,#656);
#659=EDGE_CURVE('E639',#652,#180,#658,.T.);
#660=ORIENTED_EDGE('',*,*,#659,.T.);
#661=ORIENTED_EDGE('',*,*,#181,.F.);
#662=DIRECTION('',(0.,0.996033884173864,0.088974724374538));
#663=VECTOR('',#662,1.);
#664=CARTESIAN_POINT('',(-1.6,-19.5480424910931,7.35495953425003));
#665=LINE('',#664,#663);
#666=CARTESIAN_POINT('',(-1.6,-19.5480424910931,7.35495953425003));
#667=VERTEX_POINT('',#666);
#668=EDGE_CURVE('E675',#174,#667,#665,.T.);
#669=ORIENTED_EDGE('',*,*,#668,.T.);
#670=CARTESIAN_POINT('',(-1.6,-19.7402278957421,9.50639272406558));
#671=DIRECTION('',(1.,0.,0.));
#672=DIRECTION('',(0.,0.433883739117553,0.900968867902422));
#673=AXIS2_PLACEMENT_3D('',#670,#671,#672);
#674=CIRCLE('',#673,2.16);
#675=CARTESIAN_POINT('',(-1.6,-17.9383440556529,10.6975327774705));
#676=VERTEX_POINT('',#675);
#677=EDGE_CURVE('E683',#667,#676,#674,.T.);
#678=ORIENTED_EDGE('',*,*,#677,.T.);
#679=DIRECTION('',(0.,-0.551453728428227,0.834205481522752));
#680=VECTOR('',#679,1.);
#681=CARTESIAN_POINT('',(-1.6,-17.9383440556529,10.6975327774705));
#682=LINE('',#681,#680);
#683=EDGE_CURVE('E665',#676,#153,#682,.T.);
#684=ORIENTED_EDGE('',*,*,#683,.T.);
#685=ORIENTED_EDGE('',*,*,#154,.F.);
#686=DIRECTION('',(0.,0.936000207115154,-0.351999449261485));
#687=VECTOR('',#686,1.);
#688=CARTESIAN_POINT('',(-1.6,-14.4209803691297,15.1081673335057));
#689=LINE('',#688,#687);
#690=CARTESIAN_POINT('',(-1.6,-14.4209803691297,15.1081673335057));
#691=VERTEX_POINT('',#690);
#692=EDGE_CURVE('E701',#147,#691,#689,.T.);
#693=ORIENTED_EDGE('',*,*,#692,.T.);
#694=CARTESIAN_POINT('',(-1.6,-13.6606615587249,17.1299277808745));
#695=DIRECTION('',(1.,0.,0.));
#696=DIRECTION('',(0.,0.781831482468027,0.623489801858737));
#697=AXIS2_PLACEMENT_3D('',#694,#695,#696);
#698=CIRCLE('',#697,2.16);
#699=CARTESIAN_POINT('',(-1.6,-11.5204040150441,17.4212997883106));
#700=VERTEX_POINT('',#699);
#701=EDGE_CURVE('E709',#691,#700,#698,.T.);
#702=ORIENTED_EDGE('',*,*,#701,.T.);
#703=DIRECTION('',(0.,-0.134894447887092,0.990859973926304));
#704=VECTOR('',#703,1.);
#705=CARTESIAN_POINT('',(-1.6,-11.5204040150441,17.4212997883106));
#706=LINE('',#705,#704);
#707=EDGE_CURVE('E691',#700,#126,#706,.T.);
#708=ORIENTED_EDGE('',*,*,#707,.T.);
#709=ORIENTED_EDGE('',*,*,#127,.F.);
#710=DIRECTION('',(0.,0.690580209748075,-0.723255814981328));
#711=VECTOR('',#710,1.);
#712=CARTESIAN_POINT('',(-1.6,-6.4376662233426,19.8690173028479));
#713=LINE('',#712,#711);
#714=CARTESIAN_POINT('',(-1.6,-6.4376662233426,19.8690173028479));
#715=VERTEX_POINT('',#714);
#716=EDGE_CURVE('E727',#120,#715,#713,.T.);
#717=ORIENTED_EDGE('',*,*,#716,.T.);
#718=CARTESIAN_POINT('',(-1.6,-4.87543366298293,21.3606705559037));
#719=DIRECTION('',(1.,0.,0.));
#720=DIRECTION('',(0.,0.974927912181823,0.222520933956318));
#721=AXIS2_PLACEMENT_3D('',#718,#719,#720);
#722=CIRCLE('',#721,2.16);
#723=CARTESIAN_POINT('',(-1.6,-2.82070667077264,20.6945647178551));
#724=VERTEX_POINT('',#723);
#725=EDGE_CURVE('E735',#715,#724,#722,.T.);
#726=ORIENTED_EDGE('',*,*,#725,.T.);
#727=DIRECTION('',(0.,0.308382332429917,0.951262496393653));
#728=VECTOR('',#727,1.);
#729=CARTESIAN_POINT('',(-1.6,-2.82070667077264,20.6945647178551));
#730=LINE('',#729,#728);
#731=EDGE_CURVE('E717',#724,#99,#730,.T.);
#732=ORIENTED_EDGE('',*,*,#731,.T.);
#733=ORIENTED_EDGE('',*,*,#100,.F.);
#734=DIRECTION('',(0.,0.308382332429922,-0.951262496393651));
#735=VECTOR('',#734,1.);
#736=CARTESIAN_POINT('',(-1.6,2.82070667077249,20.6945647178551));
#737=LINE('',#736,#735);
#738=CARTESIAN_POINT('',(-1.6,2.8207066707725,20.6945647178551));
#739=VERTEX_POINT('',#738);
#740=EDGE_CURVE('E751',#93,#739,#737,.T.);
#741=ORIENTED_EDGE('',*,*,#740,.T.);
#742=CARTESIAN_POINT('',(-1.6,4.87543366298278,21.3606705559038));
#743=DIRECTION('',(1.,0.,0.));
#744=DIRECTION('',(0.,0.974927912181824,-0.222520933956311));
#745=AXIS2_PLACEMENT_3D('',#742,#743,#744);
#746=CIRCLE('',#745,2.16);
#747=CARTESIAN_POINT('',(-1.6,6.43766622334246,19.8690173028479));
#748=VERTEX_POINT('',#747);
#749=EDGE_CURVE('E758',#739,#748,#746,.T.);
#750=ORIENTED_EDGE('',*,*,#749,.T.);
#751=DIRECTION('',(0.,0.690580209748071,0.723255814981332));
#752=VECTOR('',#751,1.);
#753=CARTESIAN_POINT('',(-1.6,6.43766622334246,19.8690173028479));
#754=LINE('',#753,#752);
#755=EDGE_CURVE('E416',#748,#72,#754,.T.);
#756=ORIENTED_EDGE('',*,*,#755,.T.);
#757=ORIENTED_EDGE('',*,*,#73,.F.);
#758=DIRECTION('',(0.,-0.134894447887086,-0.990859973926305));
#759=VECTOR('',#758,1.);
#760=CARTESIAN_POINT('',(-1.6,11.520404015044,17.4212997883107));
#761=LINE('',#760,#759);
#762=EDGE_CURVE('E388',#66,#434,#761,.T.);
#763=ORIENTED_EDGE('',*,*,#762,.T.);
#764=EDGE_LOOP('',(#438,#444,#445,#453,#462,#468,#469,#477,#486,#492,#493,#501,#510,#516,#517,
#525,#534,#540,#541,#549,#558,#564,#565,#573,#582,#588,#589,#597,#606,#612,#613,#621,#630,#636,
#637,#645,#654,#660,#661,#669,#678,#684,#685,#693,#702,#708,#709,#717,#726,#732,#733,#741,#750,
#756,#757,#763));
#765=FACE_BOUND('',#764,.T.);
#766=ADVANCED_FACE('F413',(#427,#765),#416,.F.);
#767=CARTESIAN_POINT('',(0.,0.,0.));
#768=DIRECTION('',(1.,0.,0.));
#769=DIRECTION('',(0.,0.,-1.));
#770=AXIS2_PLACEMENT_3D('',#767,#768,#769);
#771=PLANE('',#770);
#772=DIRECTION('',(0.,0.936000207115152,0.35199944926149));
#773=VECTOR('',#772,1.);
#774=CARTESIAN_POINT('',(0.,14.4209803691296,15.1081673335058));
#775=LINE('',#774,#773);
#776=CARTESIAN_POINT('',(0.,14.4209803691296,15.1081673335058));
#777=VERTEX_POINT('',#776);
#778=EDGE_CURVE('E400',#777,#31,#775,.T.);
#779=ORIENTED_EDGE('',*,*,#778,.F.);
#780=CARTESIAN_POINT('',(0.,13.6606615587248,17.1299277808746));
#781=DIRECTION('',(1.,0.,0.));
#782=DIRECTION('',(0.,0.781831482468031,-0.623489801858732));
#783=AXIS2_PLACEMENT_3D('',#780,#781,#782);
#784=CIRCLE('',#783,2.16);
#785=CARTESIAN_POINT('',(0.,11.520404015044,17.4212997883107));
#786=VERTEX_POINT('',#785);
#787=EDGE_CURVE('E768',#786,#777,#784,.T.);
#788=ORIENTED_EDGE('',*,*,#787,.F.);
#789=DIRECTION('',(0.,-0.134894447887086,-0.990859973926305));
#790=VECTOR('',#789,1.);
#791=CARTESIAN_POINT('',(0.,11.520404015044,17.4212997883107));
#792=LINE('',#791,#790);
#793=EDGE_CURVE('E748',#68,#786,#792,.T.);
#794=ORIENTED_EDGE('',*,*,#793,.F.);
#795=ORIENTED_EDGE('',*,*,#83,.T.);
#796=DIRECTION('',(0.,0.690580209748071,0.723255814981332));
#797=VECTOR('',#796,1.);
#798=CARTESIAN_POINT('',(0.,6.43766622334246,19.8690173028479));
#799=LINE('',#798,#797);
#800=CARTESIAN_POINT('',(0.,6.43766622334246,19.8690173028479));
#801=VERTEX_POINT('',#800);
#802=EDGE_CURVE('E749',#801,#80,#799,.T.);
#803=ORIENTED_EDGE('',*,*,#802,.F.);
#804=CARTESIAN_POINT('',(0.,4.87543366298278,21.3606705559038));
#805=DIRECTION('',(1.,0.,0.));
#806=DIRECTION('',(0.,0.974927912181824,-0.222520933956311));
#807=AXIS2_PLACEMENT_3D('',#804,#805,#806);
#808=CIRCLE('',#807,2.16);
#809=CARTESIAN_POINT('',(0.,2.8207066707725,20.6945647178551));
#810=VERTEX_POINT('',#809);
#811=EDGE_CURVE('E752',#810,#801,#808,.T.);
#812=ORIENTED_EDGE('',*,*,#811,.F.);
#813=DIRECTION('',(0.,0.308382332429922,-0.951262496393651));
#814=VECTOR('',#813,1.);
#815=CARTESIAN_POINT('',(0.,2.82070667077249,20.6945647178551));
#816=LINE('',#815,#814);
#817=EDGE_CURVE('E724',#95,#810,#816,.T.);
#818=ORIENTED_EDGE('',*,*,#817,.F.);
#819=ORIENTED_EDGE('',*,*,#110,.T.);
#820=DIRECTION('',(0.,0.308382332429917,0.951262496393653));
#821=VECTOR('',#820,1.);
#822=CARTESIAN_POINT('',(0.,-2.82070667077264,20.6945647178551));
#823=LINE('',#822,#821);
#824=CARTESIAN_POINT('',(0.,-2.82070667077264,20.6945647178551));
#825=VERTEX_POINT('',#824);
#826=EDGE_CURVE('E725',#825,#107,#823,.T.);
#827=ORIENTED_EDGE('',*,*,#826,.F.);
#828=CARTESIAN_POINT('',(0.,-4.87543366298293,21.3606705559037));
#829=DIRECTION('',(1.,0.,0.));
#830=DIRECTION('',(0.,0.974927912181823,0.222520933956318));
#831=AXIS2_PLACEMENT_3D('',#828,#829,#830);
#832=CIRCLE('',#831,2.16);
#833=CARTESIAN_POINT('',(0.,-6.4376662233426,19.8690173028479));
#834=VERTEX_POINT('',#833);
#835=EDGE_CURVE('E728',#834,#825,#832,.T.);
#836=ORIENTED_EDGE('',*,*,#835,.F.);
#837=DIRECTION('',(0.,0.690580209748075,-0.723255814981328));
#838=VECTOR('',#837,1.);
#839=CARTESIAN_POINT('',(0.,-6.4376662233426,19.8690173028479));
#840=LINE('',#839,#838);
#841=EDGE_CURVE('E698',#122,#834,#840,.T.);
#842=ORIENTED_EDGE('',*,*,#841,.F.);
#843=ORIENTED_EDGE('',*,*,#137,.T.);
#844=DIRECTION('',(0.,-0.134894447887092,0.990859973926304));
#845=VECTOR('',#844,1.);
#846=CARTESIAN_POINT('',(0.,-11.5204040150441,17.4212997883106));
#847=LINE('',#846,#845);
#848=CARTESIAN_POINT('',(0.,-11.5204040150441,17.4212997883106));
#849=VERTEX_POINT('',#848);
#850=EDGE_CURVE('E699',#849,#134,#847,.T.);
#851=ORIENTED_EDGE('',*,*,#850,.F.);
#852=CARTESIAN_POINT('',(0.,-13.6606615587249,17.1299277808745));
#853=DIRECTION('',(1.,0.,0.));
#854=DIRECTION('',(0.,0.781831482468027,0.623489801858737));
#855=AXIS2_PLACEMENT_3D('',#852,#853,#854);
#856=CIRCLE('',#855,2.16);
#857=CARTESIAN_POINT('',(0.,-14.4209803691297,15.1081673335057));
#858=VERTEX_POINT('',#857);
#859=EDGE_CURVE('E702',#858,#849,#856,.T.);
#860=ORIENTED_EDGE('',*,*,#859,.F.);
#861=DIRECTION('',(0.,0.936000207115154,-0.351999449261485));
#862=VECTOR('',#861,1.);
#863=CARTESIAN_POINT('',(0.,-14.4209803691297,15.1081673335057));
#864=LINE('',#863,#862);
#865=EDGE_CURVE('E672',#149,#858,#864,.T.);
#866=ORIENTED_EDGE('',*,*,#865,.F.);
#867=ORIENTED_EDGE('',*,*,#164,.T.);
#868=DIRECTION('',(0.,-0.551453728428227,0.834205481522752));
#869=VECTOR('',#868,1.);
#870=CARTESIAN_POINT('',(0.,-17.9383440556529,10.6975327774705));
#871=LINE('',#870,#869);
#872=CARTESIAN_POINT('',(0.,-17.9383440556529,10.6975327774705));
#873=VERTEX_POINT('',#872);
#874=EDGE_CURVE('E673',#873,#161,#871,.T.);
#875=ORIENTED_EDGE('',*,*,#874,.F.);
#876=CARTESIAN_POINT('',(0.,-19.7402278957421,9.50639272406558));
#877=DIRECTION('',(1.,0.,0.));
#878=DIRECTION('',(0.,0.433883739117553,0.900968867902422));
#879=AXIS2_PLACEMENT_3D('',#876,#877,#878);
#880=CIRCLE('',#879,2.16);
#881=CARTESIAN_POINT('',(0.,-19.5480424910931,7.35495953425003));
#882=VERTEX_POINT('',#881);
#883=EDGE_CURVE('E676',#882,#873,#880,.T.);
#884=ORIENTED_EDGE('',*,*,#883,.F.);
#885=DIRECTION('',(0.,0.996033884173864,0.088974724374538));
#886=VECTOR('',#885,1.);
#887=CARTESIAN_POINT('',(0.,-19.5480424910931,7.35495953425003));
#888=LINE('',#887,#886);
#889=EDGE_CURVE('E646',#176,#882,#888,.T.);
#890=ORIENTED_EDGE('',*,*,#889,.F.);
#891=ORIENTED_EDGE('',*,*,#191,.T.);
#892=DIRECTION('',(0.,-0.858790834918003,0.512326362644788));
#893=VECTOR('',#892,1.);
#894=CARTESIAN_POINT('',(0.,-20.8033750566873,1.85498820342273));
#895=LINE('',#894,#893);
#896=CARTESIAN_POINT('',(0.,-20.8033750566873,1.85498820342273));
#897=VERTEX_POINT('',#896);
#898=EDGE_CURVE('E647',#897,#188,#895,.T.);
#899=ORIENTED_EDGE('',*,*,#898,.F.);
#900=CARTESIAN_POINT('',(0.,-21.91,-1.52996712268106E-13));
#901=DIRECTION('',(1.,0.,0.));
#902=DIRECTION('',(0.,0.,1.));
#903=AXIS2_PLACEMENT_3D('',#900,#901,#902);
#904=CIRCLE('',#903,2.16);
#905=CARTESIAN_POINT('',(0.,-20.8033750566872,-1.85498820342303));
#906=VERTEX_POINT('',#905);
#907=EDGE_CURVE('E650',#906,#897,#904,.T.);
#908=ORIENTED_EDGE('',*,*,#907,.F.);
#909=DIRECTION('',(0.,0.858790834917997,0.512326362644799));
#910=VECTOR('',#909,1.);
#911=CARTESIAN_POINT('',(0.,-20.8033750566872,-1.85498820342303));
#912=LINE('',#911,#910);
#913=EDGE_CURVE('E620',#203,#906,#912,.T.);
#914=ORIENTED_EDGE('',*,*,#913,.F.);
#915=ORIENTED_EDGE('',*,*,#218,.T.);
#916=DIRECTION('',(0.,-0.996033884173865,0.0889747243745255));
#917=VECTOR('',#916,1.);
#918=CARTESIAN_POINT('',(0.,-19.548042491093,-7.3549595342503));
#919=LINE('',#918,#917);
#920=CARTESIAN_POINT('',(0.,-19.548042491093,-7.3549595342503));
#921=VERTEX_POINT('',#920);
#922=EDGE_CURVE('E621',#921,#215,#919,.T.);
#923=ORIENTED_EDGE('',*,*,#922,.F.);
#924=CARTESIAN_POINT('',(0.,-19.7402278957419,-9.50639272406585));
#925=DIRECTION('',(1.,0.,0.));
#926=DIRECTION('',(0.,-0.433883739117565,0.900968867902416));
#927=AXIS2_PLACEMENT_3D('',#924,#925,#926);
#928=CIRCLE('',#927,2.16);
#929=CARTESIAN_POINT('',(0.,-17.9383440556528,-10.6975327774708));
#930=VERTEX_POINT('',#929);
#931=EDGE_CURVE('E624',#930,#921,#928,.T.);
#932=ORIENTED_EDGE('',*,*,#931,.F.);
#933=DIRECTION('',(0.,0.551453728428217,0.834205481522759));
#934=VECTOR('',#933,1.);
#935=CARTESIAN_POINT('',(0.,-17.9383440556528,-10.6975327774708));
#936=LINE('',#935,#934);
#937=EDGE_CURVE('E594',#230,#930,#936,.T.);
#938=ORIENTED_EDGE('',*,*,#937,.F.);
#939=ORIENTED_EDGE('',*,*,#245,.T.);
#940=DIRECTION('',(0.,-0.93600020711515,-0.351999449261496));
#941=VECTOR('',#940,1.);
#942=CARTESIAN_POINT('',(0.,-14.4209803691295,-15.1081673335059));
#943=LINE('',#942,#941);
#944=CARTESIAN_POINT('',(0.,-14.4209803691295,-15.1081673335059));
#945=VERTEX_POINT('',#944);
#946=EDGE_CURVE('E595',#945,#242,#943,.T.);
#947=ORIENTED_EDGE('',*,*,#946,.F.);
#948=CARTESIAN_POINT('',(0.,-13.6606615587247,-17.1299277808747));
#949=DIRECTION('',(1.,0.,0.));
#950=DIRECTION('',(0.,-0.781831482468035,0.623489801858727));
#951=AXIS2_PLACEMENT_3D('',#948,#949,#950);
#952=CIRCLE('',#951,2.16);
#953=CARTESIAN_POINT('',(0.,-11.5204040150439,-17.4212997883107));
#954=VERTEX_POINT('',#953);
#955=EDGE_CURVE('E598',#954,#945,#952,.T.);
#956=ORIENTED_EDGE('',*,*,#955,.F.);
#957=DIRECTION('',(0.,0.13489444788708,0.990859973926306));
#958=VECTOR('',#957,1.);
#959=CARTESIAN_POINT('',(0.,-11.5204040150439,-17.4212997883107));
#960=LINE('',#959,#958);
#961=EDGE_CURVE('E568',#257,#954,#960,.T.);
#962=ORIENTED_EDGE('',*,*,#961,.F.);
#963=ORIENTED_EDGE('',*,*,#272,.T.);
#964=DIRECTION('',(0.,-0.690580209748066,-0.723255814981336));
#965=VECTOR('',#964,1.);
#966=CARTESIAN_POINT('',(0.,-6.43766622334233,-19.869017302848));
#967=LINE('',#966,#965);
#968=CARTESIAN_POINT('',(0.,-6.43766622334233,-19.869017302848));
#969=VERTEX_POINT('',#968);
#970=EDGE_CURVE('E569',#969,#269,#967,.T.);
#971=ORIENTED_EDGE('',*,*,#970,.F.);
#972=CARTESIAN_POINT('',(0.,-4.87543366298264,-21.3606705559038));
#973=DIRECTION('',(1.,0.,0.));
#974=DIRECTION('',(0.,-0.974927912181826,0.222520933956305));
#975=AXIS2_PLACEMENT_3D('',#972,#973,#974);
#976=CIRCLE('',#975,2.16);
#977=CARTESIAN_POINT('',(0.,-2.82070667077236,-20.6945647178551));
#978=VERTEX_POINT('',#977);
#979=EDGE_CURVE('E572',#978,#969,#976,.T.);
#980=ORIENTED_EDGE('',*,*,#979,.F.);
#981=DIRECTION('',(0.,-0.308382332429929,0.951262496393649));
#982=VECTOR('',#981,1.);
#983=CARTESIAN_POINT('',(0.,-2.82070667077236,-20.6945647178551));
#984=LINE('',#983,#982);
#985=EDGE_CURVE('E542',#284,#978,#984,.T.);
#986=ORIENTED_EDGE('',*,*,#985,.F.);
#987=ORIENTED_EDGE('',*,*,#299,.T.);
#988=DIRECTION('',(0.,-0.308382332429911,-0.951262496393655));
#989=VECTOR('',#988,1.);
#990=CARTESIAN_POINT('',(0.,2.82070667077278,-20.6945647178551));
#991=LINE('',#990,#989);
#992=CARTESIAN_POINT('',(0.,2.82070667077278,-20.6945647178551));
#993=VERTEX_POINT('',#992);
#994=EDGE_CURVE('E543',#993,#296,#991,.T.);
#995=ORIENTED_EDGE('',*,*,#994,.F.);
#996=CARTESIAN_POINT('',(0.,4.87543366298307,-21.3606705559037));
#997=DIRECTION('',(1.,0.,0.));
#998=DIRECTION('',(0.,-0.974927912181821,-0.222520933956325));
#999=AXIS2_PLACEMENT_3D('',#996,#997,#998);
#1000=CIRCLE('',#999,2.16);
#1001=CARTESIAN_POINT('',(0.,6.43766622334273,-19.8690173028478));
#1002=VERTEX_POINT('',#1001);
#1003=EDGE_CURVE('E546',#1002,#993,#1000,.T.);
#1004=ORIENTED_EDGE('',*,*,#1003,.F.);
#1005=DIRECTION('',(0.,-0.69058020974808,0.723255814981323));
#1006=VECTOR('',#1005,1.);
#1007=CARTESIAN_POINT('',(0.,6.43766622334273,-19.8690173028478));
#1008=LINE('',#1007,#1006);
#1009=EDGE_CURVE('E517',#311,#1002,#1008,.T.);
#1010=ORIENTED_EDGE('',*,*,#1009,.F.);
#1011=ORIENTED_EDGE('',*,*,#326,.T.);
#1012=DIRECTION('',(0.,0.134894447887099,-0.990859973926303));
#1013=VECTOR('',#1012,1.);
#1014=CARTESIAN_POINT('',(0.,11.5204040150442,-17.4212997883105));
#1015=LINE('',#1014,#1013);
#1016=CARTESIAN_POINT('',(0.,11.5204040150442,-17.4212997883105));
#1017=VERTEX_POINT('',#1016);
#1018=EDGE_CURVE('E518',#1017,#323,#1015,.T.);
#1019=ORIENTED_EDGE('',*,*,#1018,.F.);
#1020=CARTESIAN_POINT('',(0.,13.6606615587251,-17.1299277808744));
#1021=DIRECTION('',(1.,0.,0.));
#1022=DIRECTION('',(0.,-0.781831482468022,-0.623489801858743));
#1023=AXIS2_PLACEMENT_3D('',#1020,#1021,#1022);
#1024=CIRCLE('',#1023,2.16);
#1025=CARTESIAN_POINT('',(0.,14.4209803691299,-15.1081673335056));
#1026=VERTEX_POINT('',#1025);
#1027=EDGE_CURVE('E521',#1026,#1017,#1024,.T.);
#1028=ORIENTED_EDGE('',*,*,#1027,.F.);
#1029=DIRECTION('',(0.,-0.936000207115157,0.351999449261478));
#1030=VECTOR('',#1029,1.);
#1031=CARTESIAN_POINT('',(0.,14.4209803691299,-15.1081673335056));
#1032=LINE('',#1031,#1030);
#1033=EDGE_CURVE('E492',#338,#1026,#1032,.T.);
#1034=ORIENTED_EDGE('',*,*,#1033,.F.);
#1035=ORIENTED_EDGE('',*,*,#353,.T.);
#1036=DIRECTION('',(0.,0.551453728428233,-0.834205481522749));
#1037=VECTOR('',#1036,1.);
#1038=CARTESIAN_POINT('',(0.,17.938344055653,-10.6975327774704));
#1039=LINE('',#1038,#1037);
#1040=CARTESIAN_POINT('',(0.,17.938344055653,-10.6975327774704));
#1041=VERTEX_POINT('',#1040);
#1042=EDGE_CURVE('E493',#1041,#350,#1039,.T.);
#1043=ORIENTED_EDGE('',*,*,#1042,.F.);
#1044=CARTESIAN_POINT('',(0.,19.7402278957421,-9.50639272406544));
#1045=DIRECTION('',(1.,0.,0.));
#1046=DIRECTION('',(0.,-0.433883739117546,-0.900968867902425));
#1047=AXIS2_PLACEMENT_3D('',#1044,#1045,#1046);
#1048=CIRCLE('',#1047,2.16);
#1049=CARTESIAN_POINT('',(0.,19.5480424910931,-7.35495953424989));
#1050=VERTEX_POINT('',#1049);
#1051=EDGE_CURVE('E496',#1050,#1041,#1048,.T.);
#1052=ORIENTED_EDGE('',*,*,#1051,.F.);
#1053=DIRECTION('',(0.,-0.996033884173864,-0.088974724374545));
#1054=VECTOR('',#1053,1.);
#1055=CARTESIAN_POINT('',(0.,19.5480424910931,-7.35495953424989));
#1056=LINE('',#1055,#1054);
#1057=EDGE_CURVE('E499',#392,#1050,#1056,.T.);
#1058=ORIENTED_EDGE('',*,*,#1057,.F.);
#1059=ORIENTED_EDGE('',*,*,#407,.T.);
#1060=DIRECTION('',(0.,0.858790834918,-0.512326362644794));
#1061=VECTOR('',#1060,1.);
#1062=CARTESIAN_POINT('',(0.,20.8033750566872,-1.85498820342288));
#1063=LINE('',#1062,#1061);
#1064=CARTESIAN_POINT('',(0.,20.8033750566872,-1.85498820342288));
#1065=VERTEX_POINT('',#1064);
#1066=EDGE_CURVE('E439',#1065,#404,#1063,.T.);
#1067=ORIENTED_EDGE('',*,*,#1066,.F.);
#1068=CARTESIAN_POINT('',(0.,21.91,0.));
#1069=DIRECTION('',(1.,0.,0.));
#1070=DIRECTION('',(0.,0.,-1.));
#1071=AXIS2_PLACEMENT_3D('',#1068,#1069,#1070);
#1072=CIRCLE('',#1071,2.16);
#1073=CARTESIAN_POINT('',(0.,20.8033750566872,1.85498820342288));
#1074=VERTEX_POINT('',#1073);
#1075=EDGE_CURVE('E443',#1074,#1065,#1072,.T.);
#1076=ORIENTED_EDGE('',*,*,#1075,.F.);
#1077=DIRECTION('',(0.,-0.858790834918,-0.512326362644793));
#1078=VECTOR('',#1077,1.);
#1079=CARTESIAN_POINT('',(0.,20.8033750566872,1.85498820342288));
#1080=LINE('',#1079,#1078);
#1081=EDGE_CURVE('E446',#369,#1074,#1080,.T.);
#1082=ORIENTED_EDGE('',*,*,#1081,.F.);
#1083=ORIENTED_EDGE('',*,*,#370,.T.);
#1084=DIRECTION('',(0.,0.996033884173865,-0.0889747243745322));
#1085=VECTOR('',#1084,1.);
#1086=CARTESIAN_POINT('',(0.,19.548042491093,7.35495953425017));
#1087=LINE('',#1086,#1085);
#1088=CARTESIAN_POINT('',(0.,19.548042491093,7.35495953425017));
#1089=VERTEX_POINT('',#1088);
#1090=EDGE_CURVE('E466',#1089,#365,#1087,.T.);
#1091=ORIENTED_EDGE('',*,*,#1090,.F.);
#1092=CARTESIAN_POINT('',(0.,19.740227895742,9.50639272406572));
#1093=DIRECTION('',(1.,0.,0.));
#1094=DIRECTION('',(0.,0.433883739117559,-0.900968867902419));
#1095=AXIS2_PLACEMENT_3D('',#1092,#1093,#1094);
#1096=CIRCLE('',#1095,2.16);
#1097=CARTESIAN_POINT('',(0.,17.9383440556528,10.6975327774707));
#1098=VERTEX_POINT('',#1097);
#1099=EDGE_CURVE('E469',#1098,#1089,#1096,.T.);
#1100=ORIENTED_EDGE('',*,*,#1099,.F.);
#1101=DIRECTION('',(0.,-0.551453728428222,-0.834205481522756));
#1102=VECTOR('',#1101,1.);
#1103=CARTESIAN_POINT('',(0.,17.9383440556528,10.6975327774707));
#1104=LINE('',#1103,#1102);
#1105=EDGE_CURVE('E472',#40,#1098,#1104,.T.);
#1106=ORIENTED_EDGE('',*,*,#1105,.F.);
#1107=ORIENTED_EDGE('',*,*,#41,.T.);
#1108=EDGE_LOOP('',(#779,#788,#794,#795,#803,#812,#818,#819,#827,#836,#842,#843,#851,#860,#866,
#867,#875,#884,#890,#891,#899,#908,#914,#915,#923,#932,#938,#939,#947,#956,#962,#963,#971,#980,
#986,#987,#995,#1004,#1010,#1011,#1019,#1028,#1034,#1035,#1043,#1052,#1058,#1059,#1067,#1076,
#1082,#1083,#1091,#1100,#1106,#1107));
#1109=FACE_BOUND('',#1108,.T.);
#1110=CARTESIAN_POINT('',(0.,0.,0.));
#1111=DIRECTION('',(1.,0.,0.));
#1112=DIRECTION('',(0.,0.,-1.));
#1113=AXIS2_PLACEMENT_3D('',#1110,#1111,#1112);
#1114=CIRCLE('',#1113,15.5);
#1115=CARTESIAN_POINT('',(0.,0.,-15.5));
#1116=VERTEX_POINT('',#1115);
#1117=EDGE_CURVE('E422',#1116,#1116,#1114,.T.);
#1118=ORIENTED_EDGE('',*,*,#1117,.F.);
#1119=EDGE_LOOP('',(#1118));
#1120=FACE_BOUND('',#1119,.T.);
#1121=ADVANCED_FACE('F789',(#1109,#1120),#771,.T.);
#1122=CARTESIAN_POINT('',(-1.6,0.,0.));
#1123=DIRECTION('',(1.,0.,0.));
#1124=DIRECTION('',(0.,0.,-1.));
#1125=AXIS2_PLACEMENT_3D('',#1122,#1123,#1124);
#1126=CYLINDRICAL_SURFACE('',#1125,15.5);
#1127=ORIENTED_EDGE('',*,*,#424,.F.);
#1128=EDGE_LOOP('',(#1127));
#1129=FACE_BOUND('',#1128,.T.);
#1130=ORIENTED_EDGE('',*,*,#1117,.T.);
#1131=EDGE_LOOP('',(#1130));
#1132=FACE_BOUND('',#1131,.T.);
#1133=ADVANCED_FACE('F1033',(#1129,#1132),#1126,.F.);
#1134=CARTESIAN_POINT('',(-1.6,20.8033750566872,-1.85498820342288));
#1135=DIRECTION('',(0.,-0.512326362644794,-0.858790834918));
#1136=DIRECTION('',(0.,0.858790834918,-0.512326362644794));
#1137=AXIS2_PLACEMENT_3D('',#1134,#1135,#1136);
#1138=PLANE('',#1137);
#1139=ORIENTED_EDGE('',*,*,#1066,.T.);
#1140=ORIENTED_EDGE('',*,*,#405,.F.);
#1141=ORIENTED_EDGE('',*,*,#491,.F.);
#1142=DIRECTION('',(1.,0.,0.));
#1143=VECTOR('',#1142,1.);
#1144=CARTESIAN_POINT('',(-1.6,20.8033750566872,-1.85498820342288));
#1145=LINE('',#1144,#1143);
#1146=EDGE_CURVE('E435',#484,#1065,#1145,.T.);
#1147=ORIENTED_EDGE('',*,*,#1146,.T.);
#1148=EDGE_LOOP('',(#1139,#1140,#1141,#1147));
#1149=FACE_BOUND('',#1148,.T.);
#1150=ADVANCED_FACE('F850',(#1149),#1138,.F.);
#1151=CARTESIAN_POINT('',(-1.6,21.91,0.));
#1152=DIRECTION('',(1.,0.,0.));
#1153=DIRECTION('',(0.,0.,-1.));
#1154=AXIS2_PLACEMENT_3D('',#1151,#1152,#1153);
#1155=CYLINDRICAL_SURFACE('',#1154,2.16);
#1156=ORIENTED_EDGE('',*,*,#1075,.T.);
#1157=ORIENTED_EDGE('',*,*,#1146,.F.);
#1158=ORIENTED_EDGE('',*,*,#485,.F.);
#1159=DIRECTION('',(1.,0.,0.));
#1160=VECTOR('',#1159,1.);
#1161=CARTESIAN_POINT('',(-1.6,20.8033750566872,1.85498820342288));
#1162=LINE('',#1161,#1160);
#1163=EDGE_CURVE('E432',#475,#1074,#1162,.T.);
#1164=ORIENTED_EDGE('',*,*,#1163,.T.);
#1165=EDGE_LOOP('',(#1156,#1157,#1158,#1164));
#1166=FACE_BOUND('',#1165,.T.);
#1167=ADVANCED_FACE('F1032',(#1166),#1155,.F.);
#1168=CARTESIAN_POINT('',(-1.6,20.8033750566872,1.85498820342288));
#1169=DIRECTION('',(0.,-0.512326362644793,0.858790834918));
#1170=DIRECTION('',(0.,-0.858790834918,-0.512326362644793));
#1171=AXIS2_PLACEMENT_3D('',#1168,#1169,#1170);
#1172=PLANE('',#1171);
#1173=ORIENTED_EDGE('',*,*,#1081,.T.);
#1174=ORIENTED_EDGE('',*,*,#1163,.F.);
#1175=ORIENTED_EDGE('',*,*,#476,.F.);
#1176=ORIENTED_EDGE('',*,*,#378,.T.);
#1177=EDGE_LOOP('',(#1173,#1174,#1175,#1176));
#1178=FACE_BOUND('',#1177,.T.);
#1179=ADVANCED_FACE('F1010',(#1178),#1172,.F.);
#1180=CARTESIAN_POINT('',(-1.6,19.548042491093,7.35495953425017));
#1181=DIRECTION('',(0.,-0.0889747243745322,-0.996033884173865));
#1182=DIRECTION('',(0.,0.996033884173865,-0.0889747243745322));
#1183=AXIS2_PLACEMENT_3D('',#1180,#1181,#1182);
#1184=PLANE('',#1183);
#1185=ORIENTED_EDGE('',*,*,#1090,.T.);
#1186=ORIENTED_EDGE('',*,*,#366,.F.);
#1187=ORIENTED_EDGE('',*,*,#467,.F.);
#1188=DIRECTION('',(1.,0.,0.));
#1189=VECTOR('',#1188,1.);
#1190=CARTESIAN_POINT('',(-1.6,19.548042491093,7.35495953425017));
#1191=LINE('',#1190,#1189);
#1192=EDGE_CURVE('E462',#460,#1089,#1191,.T.);
#1193=ORIENTED_EDGE('',*,*,#1192,.T.);
#1194=EDGE_LOOP('',(#1185,#1186,#1187,#1193));
#1195=FACE_BOUND('',#1194,.T.);
#1196=ADVANCED_FACE('F1013',(#1195),#1184,.F.);
#1197=CARTESIAN_POINT('',(-1.6,19.740227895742,9.50639272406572));
#1198=DIRECTION('',(1.,0.,0.));
#1199=DIRECTION('',(0.,0.,-1.));
#1200=AXIS2_PLACEMENT_3D('',#1197,#1198,#1199);
#1201=CYLINDRICAL_SURFACE('',#1200,2.16);
#1202=ORIENTED_EDGE('',*,*,#1099,.T.);
#1203=ORIENTED_EDGE('',*,*,#1192,.F.);
#1204=ORIENTED_EDGE('',*,*,#461,.F.);
#1205=DIRECTION('',(1.,0.,0.));
#1206=VECTOR('',#1205,1.);
#1207=CARTESIAN_POINT('',(-1.6,17.9383440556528,10.6975327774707));
#1208=LINE('',#1207,#1206);
#1209=EDGE_CURVE('E459',#451,#1098,#1208,.T.);
#1210=ORIENTED_EDGE('',*,*,#1209,.T.);
#1211=EDGE_LOOP('',(#1202,#1203,#1204,#1210));
#1212=FACE_BOUND('',#1211,.T.);
#1213=ADVANCED_FACE('F1015',(#1212),#1201,.F.);
#1214=CARTESIAN_POINT('',(-1.6,17.9383440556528,10.6975327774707));
#1215=DIRECTION('',(0.,-0.834205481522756,0.551453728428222));
#1216=DIRECTION('',(0.,-0.551453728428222,-0.834205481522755));
#1217=AXIS2_PLACEMENT_3D('',#1214,#1215,#1216);
#1218=PLANE('',#1217);
#1219=ORIENTED_EDGE('',*,*,#1105,.T.);
#1220=ORIENTED_EDGE('',*,*,#1209,.F.);
#1221=ORIENTED_EDGE('',*,*,#452,.F.);
#1222=ORIENTED_EDGE('',*,*,#49,.T.);
#1223=EDGE_LOOP('',(#1219,#1220,#1221,#1222));
#1224=FACE_BOUND('',#1223,.T.);
#1225=ADVANCED_FACE('F1017',(#1224),#1218,.F.);
#1226=CARTESIAN_POINT('',(-1.6,17.938344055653,-10.6975327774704));
#1227=DIRECTION('',(0.,-0.834205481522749,-0.551453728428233));
#1228=DIRECTION('',(0.,0.551453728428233,-0.834205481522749));
#1229=AXIS2_PLACEMENT_3D('',#1226,#1227,#1228);
#1230=PLANE('',#1229);
#1231=ORIENTED_EDGE('',*,*,#1042,.T.);
#1232=ORIENTED_EDGE('',*,*,#351,.F.);
#1233=ORIENTED_EDGE('',*,*,#515,.F.);
#1234=DIRECTION('',(1.,0.,0.));
#1235=VECTOR('',#1234,1.);
#1236=CARTESIAN_POINT('',(-1.6,17.938344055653,-10.6975327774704));
#1237=LINE('',#1236,#1235);
#1238=EDGE_CURVE('E487',#508,#1041,#1237,.T.);
#1239=ORIENTED_EDGE('',*,*,#1238,.T.);
#1240=EDGE_LOOP('',(#1231,#1232,#1233,#1239));
#1241=FACE_BOUND('',#1240,.T.);
#1242=ADVANCED_FACE('F1019',(#1241),#1230,.F.);
#1243=CARTESIAN_POINT('',(-1.6,19.7402278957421,-9.50639272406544));
#1244=DIRECTION('',(1.,0.,0.));
#1245=DIRECTION('',(0.,0.,-1.));
#1246=AXIS2_PLACEMENT_3D('',#1243,#1244,#1245);
#1247=CYLINDRICAL_SURFACE('',#1246,2.16);
#1248=ORIENTED_EDGE('',*,*,#1051,.T.);
#1249=ORIENTED_EDGE('',*,*,#1238,.F.);
#1250=ORIENTED_EDGE('',*,*,#509,.F.);
#1251=DIRECTION('',(1.,0.,0.));
#1252=VECTOR('',#1251,1.);
#1253=CARTESIAN_POINT('',(-1.6,19.5480424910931,-7.35495953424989));
#1254=LINE('',#1253,#1252);
#1255=EDGE_CURVE('E484',#499,#1050,#1254,.T.);
#1256=ORIENTED_EDGE('',*,*,#1255,.T.);
#1257=EDGE_LOOP('',(#1248,#1249,#1250,#1256));
#1258=FACE_BOUND('',#1257,.T.);
#1259=ADVANCED_FACE('F1025',(#1258),#1247,.F.);
#1260=CARTESIAN_POINT('',(-1.6,19.5480424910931,-7.35495953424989));
#1261=DIRECTION('',(0.,-0.088974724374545,0.996033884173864));
#1262=DIRECTION('',(0.,-0.996033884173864,-0.088974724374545));
#1263=AXIS2_PLACEMENT_3D('',#1260,#1261,#1262);
#1264=PLANE('',#1263);
#1265=ORIENTED_EDGE('',*,*,#1057,.T.);
#1266=ORIENTED_EDGE('',*,*,#1255,.F.);
#1267=ORIENTED_EDGE('',*,*,#500,.F.);
#1268=ORIENTED_EDGE('',*,*,#393,.T.);
#1269=EDGE_LOOP('',(#1265,#1266,#1267,#1268));
#1270=FACE_BOUND('',#1269,.T.);
#1271=ADVANCED_FACE('F1090',(#1270),#1264,.F.);
#1272=CARTESIAN_POINT('',(-1.6,11.5204040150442,-17.4212997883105));
#1273=DIRECTION('',(0.,-0.990859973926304,-0.134894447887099));
#1274=DIRECTION('',(0.,0.134894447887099,-0.990859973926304));
#1275=AXIS2_PLACEMENT_3D('',#1272,#1273,#1274);
#1276=PLANE('',#1275);
#1277=ORIENTED_EDGE('',*,*,#1018,.T.);
#1278=ORIENTED_EDGE('',*,*,#324,.F.);
#1279=ORIENTED_EDGE('',*,*,#539,.F.);
#1280=DIRECTION('',(1.,0.,0.));
#1281=VECTOR('',#1280,1.);
#1282=CARTESIAN_POINT('',(-1.6,11.5204040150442,-17.4212997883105));
#1283=LINE('',#1282,#1281);
#1284=EDGE_CURVE('E512',#532,#1017,#1283,.T.);
#1285=ORIENTED_EDGE('',*,*,#1284,.T.);
#1286=EDGE_LOOP('',(#1277,#1278,#1279,#1285));
#1287=FACE_BOUND('',#1286,.T.);
#1288=ADVANCED_FACE('F970',(#1287),#1276,.F.);
#1289=CARTESIAN_POINT('',(-1.6,13.6606615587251,-17.1299277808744));
#1290=DIRECTION('',(1.,0.,0.));
#1291=DIRECTION('',(0.,0.,-1.));
#1292=AXIS2_PLACEMENT_3D('',#1289,#1290,#1291);
#1293=CYLINDRICAL_SURFACE('',#1292,2.16);
#1294=ORIENTED_EDGE('',*,*,#1027,.T.);
#1295=ORIENTED_EDGE('',*,*,#1284,.F.);
#1296=ORIENTED_EDGE('',*,*,#533,.F.);
#1297=DIRECTION('',(1.,0.,0.));
#1298=VECTOR('',#1297,1.);
#1299=CARTESIAN_POINT('',(-1.6,14.4209803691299,-15.1081673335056));
#1300=LINE('',#1299,#1298);
#1301=EDGE_CURVE('E509',#523,#1026,#1300,.T.);
#1302=ORIENTED_EDGE('',*,*,#1301,.T.);
#1303=EDGE_LOOP('',(#1294,#1295,#1296,#1302));
#1304=FACE_BOUND('',#1303,.T.);
#1305=ADVANCED_FACE('F973',(#1304),#1293,.F.);
#1306=CARTESIAN_POINT('',(-1.6,14.4209803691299,-15.1081673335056));
#1307=DIRECTION('',(0.,0.351999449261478,0.936000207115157));
#1308=DIRECTION('',(0.,-0.936000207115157,0.351999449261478));
#1309=AXIS2_PLACEMENT_3D('',#1306,#1307,#1308);
#1310=PLANE('',#1309);
#1311=ORIENTED_EDGE('',*,*,#1033,.T.);
#1312=ORIENTED_EDGE('',*,*,#1301,.F.);
#1313=ORIENTED_EDGE('',*,*,#524,.F.);
#1314=ORIENTED_EDGE('',*,*,#339,.T.);
#1315=EDGE_LOOP('',(#1311,#1312,#1313,#1314));
#1316=FACE_BOUND('',#1315,.T.);
#1317=ADVANCED_FACE('F974',(#1316),#1310,.F.);
#1318=CARTESIAN_POINT('',(-1.6,2.82070667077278,-20.6945647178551));
#1319=DIRECTION('',(0.,-0.951262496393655,0.308382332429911));
#1320=DIRECTION('',(0.,-0.308382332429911,-0.951262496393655));
#1321=AXIS2_PLACEMENT_3D('',#1318,#1319,#1320);
#1322=PLANE('',#1321);
#1323=ORIENTED_EDGE('',*,*,#994,.T.);
#1324=ORIENTED_EDGE('',*,*,#297,.F.);
#1325=ORIENTED_EDGE('',*,*,#563,.F.);
#1326=DIRECTION('',(1.,0.,0.));
#1327=VECTOR('',#1326,1.);
#1328=CARTESIAN_POINT('',(-1.6,2.82070667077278,-20.6945647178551));
#1329=LINE('',#1328,#1327);
#1330=EDGE_CURVE('E537',#556,#993,#1329,.T.);
#1331=ORIENTED_EDGE('',*,*,#1330,.T.);
#1332=EDGE_LOOP('',(#1323,#1324,#1325,#1331));
#1333=FACE_BOUND('',#1332,.T.);
#1334=ADVANCED_FACE('F960',(#1333),#1322,.F.);
#1335=CARTESIAN_POINT('',(-1.6,4.87543366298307,-21.3606705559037));
#1336=DIRECTION('',(1.,0.,0.));
#1337=DIRECTION('',(0.,0.,-1.));
#1338=AXIS2_PLACEMENT_3D('',#1335,#1336,#1337);
#1339=CYLINDRICAL_SURFACE('',#1338,2.16);
#1340=ORIENTED_EDGE('',*,*,#1003,.T.);
#1341=ORIENTED_EDGE('',*,*,#1330,.F.);
#1342=ORIENTED_EDGE('',*,*,#557,.F.);
#1343=DIRECTION('',(1.,0.,0.));
#1344=VECTOR('',#1343,1.);
#1345=CARTESIAN_POINT('',(-1.6,6.43766622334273,-19.8690173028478));
#1346=LINE('',#1345,#1344);
#1347=EDGE_CURVE('E534',#547,#1002,#1346,.T.);
#1348=ORIENTED_EDGE('',*,*,#1347,.T.);
#1349=EDGE_LOOP('',(#1340,#1341,#1342,#1348));
#1350=FACE_BOUND('',#1349,.T.);
#1351=ADVANCED_FACE('F963',(#1350),#1339,.F.);
#1352=CARTESIAN_POINT('',(-1.6,6.43766622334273,-19.8690173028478));
#1353=DIRECTION('',(0.,0.723255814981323,0.69058020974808));
#1354=DIRECTION('',(0.,-0.69058020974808,0.723255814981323));
#1355=AXIS2_PLACEMENT_3D('',#1352,#1353,#1354);
#1356=PLANE('',#1355);
#1357=ORIENTED_EDGE('',*,*,#1009,.T.);
#1358=ORIENTED_EDGE('',*,*,#1347,.F.);
#1359=ORIENTED_EDGE('',*,*,#548,.F.);
#1360=ORIENTED_EDGE('',*,*,#312,.T.);
#1361=EDGE_LOOP('',(#1357,#1358,#1359,#1360));
#1362=FACE_BOUND('',#1361,.T.);
#1363=ADVANCED_FACE('F965',(#1362),#1356,.F.);
#1364=CARTESIAN_POINT('',(-1.6,-6.43766622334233,-19.869017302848));
#1365=DIRECTION('',(0.,-0.723255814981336,0.690580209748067));
#1366=DIRECTION('',(0.,-0.690580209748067,-0.723255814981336));
#1367=AXIS2_PLACEMENT_3D('',#1364,#1365,#1366);
#1368=PLANE('',#1367);
#1369=ORIENTED_EDGE('',*,*,#970,.T.);
#1370=ORIENTED_EDGE('',*,*,#270,.F.);
#1371=ORIENTED_EDGE('',*,*,#587,.F.);
#1372=DIRECTION('',(1.,0.,0.));
#1373=VECTOR('',#1372,1.);
#1374=CARTESIAN_POINT('',(-1.6,-6.43766622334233,-19.869017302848));
#1375=LINE('',#1374,#1373);
#1376=EDGE_CURVE('E563',#580,#969,#1375,.T.);
#1377=ORIENTED_EDGE('',*,*,#1376,.T.);
#1378=EDGE_LOOP('',(#1369,#1370,#1371,#1377));
#1379=FACE_BOUND('',#1378,.T.);
#1380=ADVANCED_FACE('F950',(#1379),#1368,.F.);
#1381=CARTESIAN_POINT('',(-1.6,-4.87543366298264,-21.3606705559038));
#1382=DIRECTION('',(1.,0.,0.));
#1383=DIRECTION('',(0.,0.,-1.));
#1384=AXIS2_PLACEMENT_3D('',#1381,#1382,#1383);
#1385=CYLINDRICAL_SURFACE('',#1384,2.16);
#1386=ORIENTED_EDGE('',*,*,#979,.T.);
#1387=ORIENTED_EDGE('',*,*,#1376,.F.);
#1388=ORIENTED_EDGE('',*,*,#581,.F.);
#1389=DIRECTION('',(1.,0.,0.));
#1390=VECTOR('',#1389,1.);
#1391=CARTESIAN_POINT('',(-1.6,-2.82070667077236,-20.6945647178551));
#1392=LINE('',#1391,#1390);
#1393=EDGE_CURVE('E560',#571,#978,#1392,.T.);
#1394=ORIENTED_EDGE('',*,*,#1393,.T.);
#1395=EDGE_LOOP('',(#1386,#1387,#1388,#1394));
#1396=FACE_BOUND('',#1395,.T.);
#1397=ADVANCED_FACE('F953',(#1396),#1385,.F.);
#1398=CARTESIAN_POINT('',(-1.6,-2.82070667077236,-20.6945647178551));
#1399=DIRECTION('',(0.,0.951262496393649,0.308382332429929));
#1400=DIRECTION('',(0.,-0.308382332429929,0.951262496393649));
#1401=AXIS2_PLACEMENT_3D('',#1398,#1399,#1400);
#1402=PLANE('',#1401);
#1403=ORIENTED_EDGE('',*,*,#985,.T.);
#1404=ORIENTED_EDGE('',*,*,#1393,.F.);
#1405=ORIENTED_EDGE('',*,*,#572,.F.);
#1406=ORIENTED_EDGE('',*,*,#285,.T.);
#1407=EDGE_LOOP('',(#1403,#1404,#1405,#1406));
#1408=FACE_BOUND('',#1407,.T.);
#1409=ADVANCED_FACE('F955',(#1408),#1402,.F.);
#1410=CARTESIAN_POINT('',(-1.6,-14.4209803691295,-15.1081673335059));
#1411=DIRECTION('',(0.,-0.351999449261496,0.93600020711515));
#1412=DIRECTION('',(0.,-0.93600020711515,-0.351999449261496));
#1413=AXIS2_PLACEMENT_3D('',#1410,#1411,#1412);
#1414=PLANE('',#1413);
#1415=ORIENTED_EDGE('',*,*,#946,.T.);
#1416=ORIENTED_EDGE('',*,*,#243,.F.);
#1417=ORIENTED_EDGE('',*,*,#611,.F.);
#1418=DIRECTION('',(1.,0.,0.));
#1419=VECTOR('',#1418,1.);
#1420=CARTESIAN_POINT('',(-1.6,-14.4209803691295,-15.1081673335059));
#1421=LINE('',#1420,#1419);
#1422=EDGE_CURVE('E589',#604,#945,#1421,.T.);
#1423=ORIENTED_EDGE('',*,*,#1422,.T.);
#1424=EDGE_LOOP('',(#1415,#1416,#1417,#1423));
#1425=FACE_BOUND('',#1424,.T.);
#1426=ADVANCED_FACE('F940',(#1425),#1414,.F.);
#1427=CARTESIAN_POINT('',(-1.6,-13.6606615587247,-17.1299277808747));
#1428=DIRECTION('',(1.,0.,0.));
#1429=DIRECTION('',(0.,0.,-1.));
#1430=AXIS2_PLACEMENT_3D('',#1427,#1428,#1429);
#1431=CYLINDRICAL_SURFACE('',#1430,2.16);
#1432=ORIENTED_EDGE('',*,*,#955,.T.);
#1433=ORIENTED_EDGE('',*,*,#1422,.F.);
#1434=ORIENTED_EDGE('',*,*,#605,.F.);
#1435=DIRECTION('',(1.,0.,0.));
#1436=VECTOR('',#1435,1.);
#1437=CARTESIAN_POINT('',(-1.6,-11.5204040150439,-17.4212997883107));
#1438=LINE('',#1437,#1436);
#1439=EDGE_CURVE('E586',#595,#954,#1438,.T.);
#1440=ORIENTED_EDGE('',*,*,#1439,.T.);
#1441=EDGE_LOOP('',(#1432,#1433,#1434,#1440));
#1442=FACE_BOUND('',#1441,.T.);
#1443=ADVANCED_FACE('F943',(#1442),#1431,.F.);
#1444=CARTESIAN_POINT('',(-1.6,-11.5204040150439,-17.4212997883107));
#1445=DIRECTION('',(0.,0.990859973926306,-0.13489444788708));
#1446=DIRECTION('',(0.,0.13489444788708,0.990859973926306));
#1447=AXIS2_PLACEMENT_3D('',#1444,#1445,#1446);
#1448=PLANE('',#1447);
#1449=ORIENTED_EDGE('',*,*,#961,.T.);
#1450=ORIENTED_EDGE('',*,*,#1439,.F.);
#1451=ORIENTED_EDGE('',*,*,#596,.F.);
#1452=ORIENTED_EDGE('',*,*,#258,.T.);
#1453=EDGE_LOOP('',(#1449,#1450,#1451,#1452));
#1454=FACE_BOUND('',#1453,.T.);
#1455=ADVANCED_FACE('F945',(#1454),#1448,.F.);
#1456=CARTESIAN_POINT('',(-1.6,-19.548042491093,-7.3549595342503));
#1457=DIRECTION('',(0.,0.0889747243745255,0.996033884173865));
#1458=DIRECTION('',(0.,-0.996033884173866,0.0889747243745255));
#1459=AXIS2_PLACEMENT_3D('',#1456,#1457,#1458);
#1460=PLANE('',#1459);
#1461=ORIENTED_EDGE('',*,*,#922,.T.);
#1462=ORIENTED_EDGE('',*,*,#216,.F.);
#1463=ORIENTED_EDGE('',*,*,#635,.F.);
#1464=DIRECTION('',(1.,0.,0.));
#1465=VECTOR('',#1464,1.);
#1466=CARTESIAN_POINT('',(-1.6,-19.548042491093,-7.3549595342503));
#1467=LINE('',#1466,#1465);
#1468=EDGE_CURVE('E615',#628,#921,#1467,.T.);
#1469=ORIENTED_EDGE('',*,*,#1468,.T.);
#1470=EDGE_LOOP('',(#1461,#1462,#1463,#1469));
#1471=FACE_BOUND('',#1470,.T.);
#1472=ADVANCED_FACE('F930',(#1471),#1460,.F.);
#1473=CARTESIAN_POINT('',(-1.6,-19.7402278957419,-9.50639272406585));
#1474=DIRECTION('',(1.,0.,0.));
#1475=DIRECTION('',(0.,0.,-1.));
#1476=AXIS2_PLACEMENT_3D('',#1473,#1474,#1475);
#1477=CYLINDRICAL_SURFACE('',#1476,2.16);
#1478=ORIENTED_EDGE('',*,*,#931,.T.);
#1479=ORIENTED_EDGE('',*,*,#1468,.F.);
#1480=ORIENTED_EDGE('',*,*,#629,.F.);
#1481=DIRECTION('',(1.,0.,0.));
#1482=VECTOR('',#1481,1.);
#1483=CARTESIAN_POINT('',(-1.6,-17.9383440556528,-10.6975327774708));
#1484=LINE('',#1483,#1482);
#1485=EDGE_CURVE('E612',#619,#930,#1484,.T.);
#1486=ORIENTED_EDGE('',*,*,#1485,.T.);
#1487=EDGE_LOOP('',(#1478,#1479,#1480,#1486));
#1488=FACE_BOUND('',#1487,.T.);
#1489=ADVANCED_FACE('F933',(#1488),#1477,.F.);
#1490=CARTESIAN_POINT('',(-1.6,-17.9383440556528,-10.6975327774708));
#1491=DIRECTION('',(0.,0.834205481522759,-0.551453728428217));
#1492=DIRECTION('',(0.,0.551453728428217,0.834205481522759));
#1493=AXIS2_PLACEMENT_3D('',#1490,#1491,#1492);
#1494=PLANE('',#1493);
#1495=ORIENTED_EDGE('',*,*,#937,.T.);
#1496=ORIENTED_EDGE('',*,*,#1485,.F.);
#1497=ORIENTED_EDGE('',*,*,#620,.F.);
#1498=ORIENTED_EDGE('',*,*,#231,.T.);
#1499=EDGE_LOOP('',(#1495,#1496,#1497,#1498));
#1500=FACE_BOUND('',#1499,.T.);
#1501=ADVANCED_FACE('F935',(#1500),#1494,.F.);
#1502=CARTESIAN_POINT('',(-1.6,-20.8033750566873,1.85498820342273));
#1503=DIRECTION('',(0.,0.512326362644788,0.858790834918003));
#1504=DIRECTION('',(0.,-0.858790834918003,0.512326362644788));
#1505=AXIS2_PLACEMENT_3D('',#1502,#1503,#1504);
#1506=PLANE('',#1505);
#1507=ORIENTED_EDGE('',*,*,#898,.T.);
#1508=ORIENTED_EDGE('',*,*,#189,.F.);
#1509=ORIENTED_EDGE('',*,*,#659,.F.);
#1510=DIRECTION('',(1.,0.,0.));
#1511=VECTOR('',#1510,1.);
#1512=CARTESIAN_POINT('',(-1.6,-20.8033750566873,1.85498820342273));
#1513=LINE('',#1512,#1511);
#1514=EDGE_CURVE('E641',#652,#897,#1513,.T.);
#1515=ORIENTED_EDGE('',*,*,#1514,.T.);
#1516=EDGE_LOOP('',(#1507,#1508,#1509,#1515));
#1517=FACE_BOUND('',#1516,.T.);
#1518=ADVANCED_FACE('F920',(#1517),#1506,.F.);
#1519=CARTESIAN_POINT('',(-1.6,-21.91,-1.52996712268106E-13));
#1520=DIRECTION('',(1.,0.,0.));
#1521=DIRECTION('',(0.,0.,-1.));
#1522=AXIS2_PLACEMENT_3D('',#1519,#1520,#1521);
#1523=CYLINDRICAL_SURFACE('',#1522,2.16);
#1524=ORIENTED_EDGE('',*,*,#907,.T.);
#1525=ORIENTED_EDGE('',*,*,#1514,.F.);
#1526=ORIENTED_EDGE('',*,*,#653,.F.);
#1527=DIRECTION('',(1.,0.,0.));
#1528=VECTOR('',#1527,1.);
#1529=CARTESIAN_POINT('',(-1.6,-20.8033750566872,-1.85498820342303));
#1530=LINE('',#1529,#1528);
#1531=EDGE_CURVE('E638',#643,#906,#1530,.T.);
#1532=ORIENTED_EDGE('',*,*,#1531,.T.);
#1533=EDGE_LOOP('',(#1524,#1525,#1526,#1532));
#1534=FACE_BOUND('',#1533,.T.);
#1535=ADVANCED_FACE('F923',(#1534),#1523,.F.);
#1536=CARTESIAN_POINT('',(-1.6,-20.8033750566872,-1.85498820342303));
#1537=DIRECTION('',(0.,0.512326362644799,-0.858790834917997));
#1538=DIRECTION('',(0.,0.858790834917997,0.512326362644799));
#1539=AXIS2_PLACEMENT_3D('',#1536,#1537,#1538);
#1540=PLANE('',#1539);
#1541=ORIENTED_EDGE('',*,*,#913,.T.);
#1542=ORIENTED_EDGE('',*,*,#1531,.F.);
#1543=ORIENTED_EDGE('',*,*,#644,.F.);
#1544=ORIENTED_EDGE('',*,*,#204,.T.);
#1545=EDGE_LOOP('',(#1541,#1542,#1543,#1544));
#1546=FACE_BOUND('',#1545,.T.);
#1547=ADVANCED_FACE('F925',(#1546),#1540,.F.);
#1548=CARTESIAN_POINT('',(-1.6,-17.9383440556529,10.6975327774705));
#1549=DIRECTION('',(0.,0.834205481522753,0.551453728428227));
#1550=DIRECTION('',(0.,-0.551453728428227,0.834205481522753));
#1551=AXIS2_PLACEMENT_3D('',#1548,#1549,#1550);
#1552=PLANE('',#1551);
#1553=ORIENTED_EDGE('',*,*,#874,.T.);
#1554=ORIENTED_EDGE('',*,*,#162,.F.);
#1555=ORIENTED_EDGE('',*,*,#683,.F.);
#1556=DIRECTION('',(1.,0.,0.));
#1557=VECTOR('',#1556,1.);
#1558=CARTESIAN_POINT('',(-1.6,-17.9383440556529,10.6975327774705));
#1559=LINE('',#1558,#1557);
#1560=EDGE_CURVE('E667',#676,#873,#1559,.T.);
#1561=ORIENTED_EDGE('',*,*,#1560,.T.);
#1562=EDGE_LOOP('',(#1553,#1554,#1555,#1561));
#1563=FACE_BOUND('',#1562,.T.);
#1564=ADVANCED_FACE('F910',(#1563),#1552,.F.);
#1565=CARTESIAN_POINT('',(-1.6,-19.7402278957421,9.50639272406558));
#1566=DIRECTION('',(1.,0.,0.));
#1567=DIRECTION('',(0.,0.,-1.));
#1568=AXIS2_PLACEMENT_3D('',#1565,#1566,#1567);
#1569=CYLINDRICAL_SURFACE('',#1568,2.16);
#1570=ORIENTED_EDGE('',*,*,#883,.T.);
#1571=ORIENTED_EDGE('',*,*,#1560,.F.);
#1572=ORIENTED_EDGE('',*,*,#677,.F.);
#1573=DIRECTION('',(1.,0.,0.));
#1574=VECTOR('',#1573,1.);
#1575=CARTESIAN_POINT('',(-1.6,-19.5480424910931,7.35495953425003));
#1576=LINE('',#1575,#1574);
#1577=EDGE_CURVE('E664',#667,#882,#1576,.T.);
#1578=ORIENTED_EDGE('',*,*,#1577,.T.);
#1579=EDGE_LOOP('',(#1570,#1571,#1572,#1578));
#1580=FACE_BOUND('',#1579,.T.);
#1581=ADVANCED_FACE('F913',(#1580),#1569,.F.);
#1582=CARTESIAN_POINT('',(-1.6,-19.5480424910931,7.35495953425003));
#1583=DIRECTION('',(0.,0.0889747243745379,-0.996033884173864));
#1584=DIRECTION('',(0.,0.996033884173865,0.088974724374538));
#1585=AXIS2_PLACEMENT_3D('',#1582,#1583,#1584);
#1586=PLANE('',#1585);
#1587=ORIENTED_EDGE('',*,*,#889,.T.);
#1588=ORIENTED_EDGE('',*,*,#1577,.F.);
#1589=ORIENTED_EDGE('',*,*,#668,.F.);
#1590=ORIENTED_EDGE('',*,*,#177,.T.);
#1591=EDGE_LOOP('',(#1587,#1588,#1589,#1590));
#1592=FACE_BOUND('',#1591,.T.);
#1593=ADVANCED_FACE('F915',(#1592),#1586,.F.);
#1594=CARTESIAN_POINT('',(-1.6,-11.5204040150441,17.4212997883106));
#1595=DIRECTION('',(0.,0.990859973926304,0.134894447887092));
#1596=DIRECTION('',(0.,-0.134894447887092,0.990859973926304));
#1597=AXIS2_PLACEMENT_3D('',#1594,#1595,#1596);
#1598=PLANE('',#1597);
#1599=ORIENTED_EDGE('',*,*,#850,.T.);
#1600=ORIENTED_EDGE('',*,*,#135,.F.);
#1601=ORIENTED_EDGE('',*,*,#707,.F.);
#1602=DIRECTION('',(1.,0.,0.));
#1603=VECTOR('',#1602,1.);
#1604=CARTESIAN_POINT('',(-1.6,-11.5204040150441,17.4212997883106));
#1605=LINE('',#1604,#1603);
#1606=EDGE_CURVE('E693',#700,#849,#1605,.T.);
#1607=ORIENTED_EDGE('',*,*,#1606,.T.);
#1608=EDGE_LOOP('',(#1599,#1600,#1601,#1607));
#1609=FACE_BOUND('',#1608,.T.);
#1610=ADVANCED_FACE('F900',(#1609),#1598,.F.);
#1611=CARTESIAN_POINT('',(-1.6,-13.6606615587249,17.1299277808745));
#1612=DIRECTION('',(1.,0.,0.));
#1613=DIRECTION('',(0.,0.,-1.));
#1614=AXIS2_PLACEMENT_3D('',#1611,#1612,#1613);
#1615=CYLINDRICAL_SURFACE('',#1614,2.16);
#1616=ORIENTED_EDGE('',*,*,#859,.T.);
#1617=ORIENTED_EDGE('',*,*,#1606,.F.);
#1618=ORIENTED_EDGE('',*,*,#701,.F.);
#1619=DIRECTION('',(1.,0.,0.));
#1620=VECTOR('',#1619,1.);
#1621=CARTESIAN_POINT('',(-1.6,-14.4209803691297,15.1081673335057));
#1622=LINE('',#1621,#1620);
#1623=EDGE_CURVE('E690',#691,#858,#1622,.T.);
#1624=ORIENTED_EDGE('',*,*,#1623,.T.);
#1625=EDGE_LOOP('',(#1616,#1617,#1618,#1624));
#1626=FACE_BOUND('',#1625,.T.);
#1627=ADVANCED_FACE('F903',(#1626),#1615,.F.);
#1628=CARTESIAN_POINT('',(-1.6,-14.4209803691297,15.1081673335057));
#1629=DIRECTION('',(0.,-0.351999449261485,-0.936000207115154));
#1630=DIRECTION('',(0.,0.936000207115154,-0.351999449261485));
#1631=AXIS2_PLACEMENT_3D('',#1628,#1629,#1630);
#1632=PLANE('',#1631);
#1633=ORIENTED_EDGE('',*,*,#865,.T.);
#1634=ORIENTED_EDGE('',*,*,#1623,.F.);
#1635=ORIENTED_EDGE('',*,*,#692,.F.);
#1636=ORIENTED_EDGE('',*,*,#150,.T.);
#1637=EDGE_LOOP('',(#1633,#1634,#1635,#1636));
#1638=FACE_BOUND('',#1637,.T.);
#1639=ADVANCED_FACE('F905',(#1638),#1632,.F.);
#1640=CARTESIAN_POINT('',(-1.6,-2.82070667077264,20.6945647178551));
#1641=DIRECTION('',(0.,0.951262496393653,-0.308382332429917));
#1642=DIRECTION('',(0.,0.308382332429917,0.951262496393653));
#1643=AXIS2_PLACEMENT_3D('',#1640,#1641,#1642);
#1644=PLANE('',#1643);
#1645=ORIENTED_EDGE('',*,*,#826,.T.);
#1646=ORIENTED_EDGE('',*,*,#108,.F.);
#1647=ORIENTED_EDGE('',*,*,#731,.F.);
#1648=DIRECTION('',(1.,0.,0.));
#1649=VECTOR('',#1648,1.);
#1650=CARTESIAN_POINT('',(-1.6,-2.82070667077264,20.6945647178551));
#1651=LINE('',#1650,#1649);
#1652=EDGE_CURVE('E719',#724,#825,#1651,.T.);
#1653=ORIENTED_EDGE('',*,*,#1652,.T.);
#1654=EDGE_LOOP('',(#1645,#1646,#1647,#1653));
#1655=FACE_BOUND('',#1654,.T.);
#1656=ADVANCED_FACE('F1284',(#1655),#1644,.F.);
#1657=CARTESIAN_POINT('',(-1.6,-4.87543366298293,21.3606705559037));
#1658=DIRECTION('',(1.,0.,0.));
#1659=DIRECTION('',(0.,0.,-1.));
#1660=AXIS2_PLACEMENT_3D('',#1657,#1658,#1659);
#1661=CYLINDRICAL_SURFACE('',#1660,2.16);
#1662=ORIENTED_EDGE('',*,*,#835,.T.);
#1663=ORIENTED_EDGE('',*,*,#1652,.F.);
#1664=ORIENTED_EDGE('',*,*,#725,.F.);
#1665=DIRECTION('',(1.,0.,0.));
#1666=VECTOR('',#1665,1.);
#1667=CARTESIAN_POINT('',(-1.6,-6.4376662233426,19.8690173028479));
#1668=LINE('',#1667,#1666);
#1669=EDGE_CURVE('E716',#715,#834,#1668,.T.);
#1670=ORIENTED_EDGE('',*,*,#1669,.T.);
#1671=EDGE_LOOP('',(#1662,#1663,#1664,#1670));
#1672=FACE_BOUND('',#1671,.T.);
#1673=ADVANCED_FACE('F1293',(#1672),#1661,.F.);
#1674=CARTESIAN_POINT('',(-1.6,-6.4376662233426,19.8690173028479));
#1675=DIRECTION('',(0.,-0.723255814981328,-0.690580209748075));
#1676=DIRECTION('',(0.,0.690580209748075,-0.723255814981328));
#1677=AXIS2_PLACEMENT_3D('',#1674,#1675,#1676);
#1678=PLANE('',#1677);
#1679=ORIENTED_EDGE('',*,*,#841,.T.);
#1680=ORIENTED_EDGE('',*,*,#1669,.F.);
#1681=ORIENTED_EDGE('',*,*,#716,.F.);
#1682=ORIENTED_EDGE('',*,*,#123,.T.);
#1683=EDGE_LOOP('',(#1679,#1680,#1681,#1682));
#1684=FACE_BOUND('',#1683,.T.);
#1685=ADVANCED_FACE('F1303',(#1684),#1678,.F.);
#1686=CARTESIAN_POINT('',(-1.6,6.43766622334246,19.8690173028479));
#1687=DIRECTION('',(0.,0.723255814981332,-0.690580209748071));
#1688=DIRECTION('',(0.,0.690580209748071,0.723255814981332));
#1689=AXIS2_PLACEMENT_3D('',#1686,#1687,#1688);
#1690=PLANE('',#1689);
#1691=ORIENTED_EDGE('',*,*,#802,.T.);
#1692=ORIENTED_EDGE('',*,*,#81,.F.);
#1693=ORIENTED_EDGE('',*,*,#755,.F.);
#1694=DIRECTION('',(1.,0.,0.));
#1695=VECTOR('',#1694,1.);
#1696=CARTESIAN_POINT('',(-1.6,6.43766622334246,19.8690173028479));
#1697=LINE('',#1696,#1695);
#1698=EDGE_CURVE('E744',#748,#801,#1697,.T.);
#1699=ORIENTED_EDGE('',*,*,#1698,.T.);
#1700=EDGE_LOOP('',(#1691,#1692,#1693,#1699));
#1701=FACE_BOUND('',#1700,.T.);
#1702=ADVANCED_FACE('F1313',(#1701),#1690,.F.);
#1703=CARTESIAN_POINT('',(-1.6,4.87543366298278,21.3606705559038));
#1704=DIRECTION('',(1.,0.,0.));
#1705=DIRECTION('',(0.,0.,-1.));
#1706=AXIS2_PLACEMENT_3D('',#1703,#1704,#1705);
#1707=CYLINDRICAL_SURFACE('',#1706,2.16);
#1708=ORIENTED_EDGE('',*,*,#811,.T.);
#1709=ORIENTED_EDGE('',*,*,#1698,.F.);
#1710=ORIENTED_EDGE('',*,*,#749,.F.);
#1711=DIRECTION('',(1.,0.,0.));
#1712=VECTOR('',#1711,1.);
#1713=CARTESIAN_POINT('',(-1.6,2.8207066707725,20.6945647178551));
#1714=LINE('',#1713,#1712);
#1715=EDGE_CURVE('E742',#739,#810,#1714,.T.);
#1716=ORIENTED_EDGE('',*,*,#1715,.T.);
#1717=EDGE_LOOP('',(#1708,#1709,#1710,#1716));
#1718=FACE_BOUND('',#1717,.T.);
#1719=ADVANCED_FACE('F1323',(#1718),#1707,.F.);
#1720=CARTESIAN_POINT('',(-1.6,2.82070667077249,20.6945647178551));
#1721=DIRECTION('',(0.,-0.951262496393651,-0.308382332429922));
#1722=DIRECTION('',(0.,0.308382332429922,-0.951262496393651));
#1723=AXIS2_PLACEMENT_3D('',#1720,#1721,#1722);
#1724=PLANE('',#1723);
#1725=ORIENTED_EDGE('',*,*,#817,.T.);
#1726=ORIENTED_EDGE('',*,*,#1715,.F.);
#1727=ORIENTED_EDGE('',*,*,#740,.F.);
#1728=ORIENTED_EDGE('',*,*,#96,.T.);
#1729=EDGE_LOOP('',(#1725,#1726,#1727,#1728));
#1730=FACE_BOUND('',#1729,.T.);
#1731=ADVANCED_FACE('F1333',(#1730),#1724,.F.);
#1732=CARTESIAN_POINT('',(-1.6,14.4209803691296,15.1081673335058));
#1733=DIRECTION('',(0.,0.35199944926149,-0.936000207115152));
#1734=DIRECTION('',(0.,0.936000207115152,0.35199944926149));
#1735=AXIS2_PLACEMENT_3D('',#1732,#1733,#1734);
#1736=PLANE('',#1735);
#1737=ORIENTED_EDGE('',*,*,#778,.T.);
#1738=ORIENTED_EDGE('',*,*,#32,.F.);
#1739=ORIENTED_EDGE('',*,*,#443,.F.);
#1740=DIRECTION('',(1.,0.,0.));
#1741=VECTOR('',#1740,1.);
#1742=CARTESIAN_POINT('',(-1.6,14.4209803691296,15.1081673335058));
#1743=LINE('',#1742,#1741);
#1744=EDGE_CURVE('E763',#436,#777,#1743,.T.);
#1745=ORIENTED_EDGE('',*,*,#1744,.T.);
#1746=EDGE_LOOP('',(#1737,#1738,#1739,#1745));
#1747=FACE_BOUND('',#1746,.T.);
#1748=ADVANCED_FACE('F781',(#1747),#1736,.F.);
#1749=CARTESIAN_POINT('',(-1.6,13.6606615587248,17.1299277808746));
#1750=DIRECTION('',(1.,0.,0.));
#1751=DIRECTION('',(0.,0.,-1.));
#1752=AXIS2_PLACEMENT_3D('',#1749,#1750,#1751);
#1753=CYLINDRICAL_SURFACE('',#1752,2.16);
#1754=ORIENTED_EDGE('',*,*,#787,.T.);
#1755=ORIENTED_EDGE('',*,*,#1744,.F.);
#1756=ORIENTED_EDGE('',*,*,#437,.F.);
#1757=DIRECTION('',(1.,0.,0.));
#1758=VECTOR('',#1757,1.);
#1759=CARTESIAN_POINT('',(-1.6,11.520404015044,17.4212997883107));
#1760=LINE('',#1759,#1758);
#1761=EDGE_CURVE('E394',#434,#786,#1760,.T.);
#1762=ORIENTED_EDGE('',*,*,#1761,.T.);
#1763=EDGE_LOOP('',(#1754,#1755,#1756,#1762));
#1764=FACE_BOUND('',#1763,.T.);
#1765=ADVANCED_FACE('F777',(#1764),#1753,.F.);
#1766=CARTESIAN_POINT('',(-1.6,11.520404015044,17.4212997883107));
#1767=DIRECTION('',(0.,-0.990859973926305,0.134894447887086));
#1768=DIRECTION('',(0.,-0.134894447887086,-0.990859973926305));
#1769=AXIS2_PLACEMENT_3D('',#1766,#1767,#1768);
#1770=PLANE('',#1769);
#1771=ORIENTED_EDGE('',*,*,#793,.T.);
#1772=ORIENTED_EDGE('',*,*,#1761,.F.);
#1773=ORIENTED_EDGE('',*,*,#762,.F.);
#1774=ORIENTED_EDGE('',*,*,#69,.T.);
#1775=EDGE_LOOP('',(#1771,#1772,#1773,#1774));
#1776=FACE_BOUND('',#1775,.T.);
#1777=ADVANCED_FACE('F391',(#1776),#1770,.F.);
#1778=CLOSED_SHELL('',(#60,#87,#114,#141,#168,#195,#222,#249,#276,#303,#330,#357,#384,#411,#766,
#1121,#1133,#1150,#1167,#1179,#1196,#1213,#1225,#1242,#1259,#1271,#1288,#1305,#1317,#1334,#1351,
#1363,#1380,#1397,#1409,#1426,#1443,#1455,#1472,#1489,#1501,#1518,#1535,#1547,#1564,#1581,#1593,
#1610,#1627,#1639,#1656,#1673,#1685,#1702,#1719,#1731,#1748,#1765,#1777));
#1779=MANIFOLD_SOLID_BREP('B2',#1778);
#1780=ADVANCED_BREP_SHAPE_REPRESENTATION('',(#18,#1779),#14);
#1781=SHAPE_DEFINITION_REPRESENTATION(#9,#1780);
ENDSEC;
END-ISO-10303-21;
